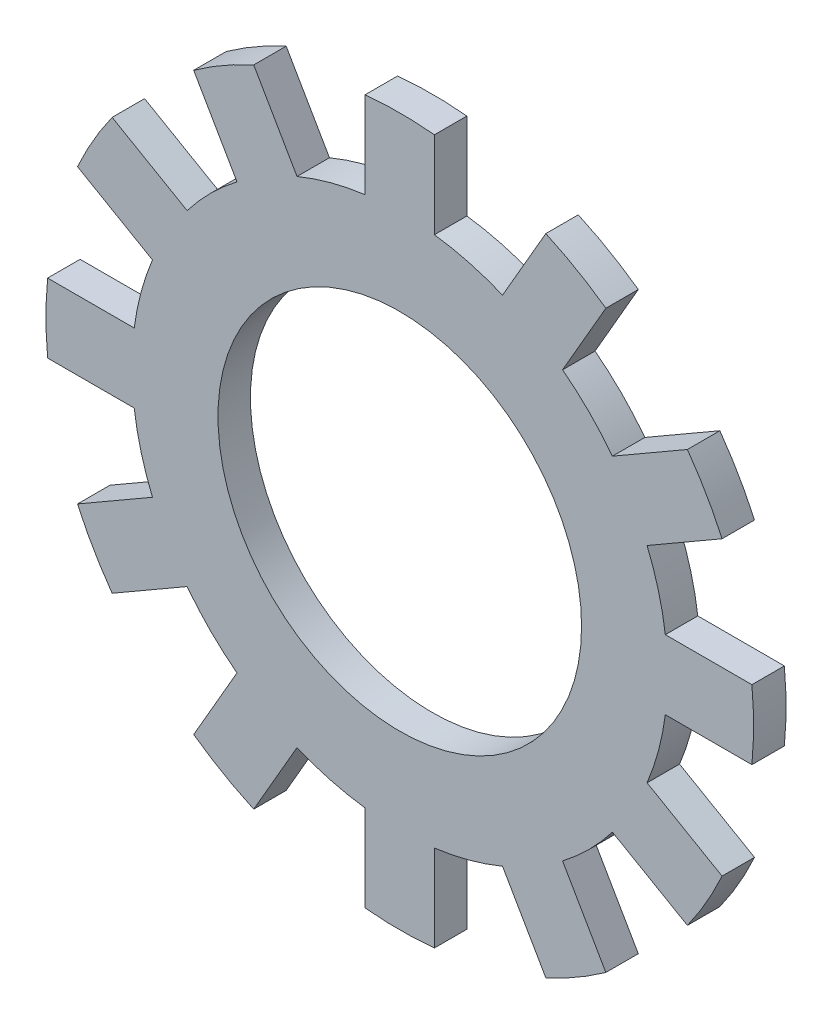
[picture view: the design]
ISO-10303-21;
HEADER;
FILE_DESCRIPTION(('STEP AP214'),'2;1');
FILE_NAME('part.step','',(''),(''),'','','');
FILE_SCHEMA(('AUTOMOTIVE_DESIGN { 1 0 10303 214 1 1 1 1 }'));
ENDSEC;
DATA;
#1=APPLICATION_CONTEXT('core data for automotive mechanical design processes');
#2=APPLICATION_PROTOCOL_DEFINITION('international standard','automotive_design',2000,#1);
#3=PRODUCT_CONTEXT('',#1,'mechanical');
#4=PRODUCT('Part','Part','',(#3));
#5=PRODUCT_RELATED_PRODUCT_CATEGORY('part','',(#4));
#6=PRODUCT_DEFINITION_FORMATION('','',#4);
#7=PRODUCT_DEFINITION_CONTEXT('part definition',#1,'design');
#8=PRODUCT_DEFINITION('design','',#6,#7);
#9=PRODUCT_DEFINITION_SHAPE('','',#8);
#10=(LENGTH_UNIT() NAMED_UNIT(*) SI_UNIT(.MILLI.,.METRE.));
#11=(NAMED_UNIT(*) PLANE_ANGLE_UNIT() SI_UNIT($,.RADIAN.));
#12=(NAMED_UNIT(*) SI_UNIT($,.STERADIAN.) SOLID_ANGLE_UNIT());
#13=UNCERTAINTY_MEASURE_WITH_UNIT(LENGTH_MEASURE(1.E-05),#10,'distance_accuracy_value','');
#14=(GEOMETRIC_REPRESENTATION_CONTEXT(3) GLOBAL_UNCERTAINTY_ASSIGNED_CONTEXT((#13)) GLOBAL_UNIT_ASSIGNED_CONTEXT((#10,
#11,#12)) REPRESENTATION_CONTEXT('',''));
#15=CARTESIAN_POINT('',(0.,0.,0.));
#16=DIRECTION('',(0.,0.,1.));
#17=DIRECTION('',(1.,0.,0.));
#18=AXIS2_PLACEMENT_3D('',#15,#16,#17);
#19=CARTESIAN_POINT('',(0.,0.,0.25));
#20=DIRECTION('',(0.,0.,-1.));
#21=DIRECTION('',(-1.,0.,0.));
#22=AXIS2_PLACEMENT_3D('',#19,#20,#21);
#23=CYLINDRICAL_SURFACE('',#22,2.0625);
#24=DIRECTION('',(0.,0.,-1.));
#25=VECTOR('',#24,1.);
#26=CARTESIAN_POINT('',(-1.25372682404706,1.63770427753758,1.41015672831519));
#27=LINE('',#26,#25);
#28=CARTESIAN_POINT('',(-1.25372682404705,1.63770427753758,0.25));
#29=VERTEX_POINT('',#28);
#30=CARTESIAN_POINT('',(-1.25372682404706,1.63770427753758,0.));
#31=VERTEX_POINT('',#30);
#32=EDGE_CURVE('E363',#29,#31,#27,.T.);
#33=ORIENTED_EDGE('',*,*,#32,.T.);
#34=CARTESIAN_POINT('',(0.,0.,0.));
#35=DIRECTION('',(0.,0.,1.));
#36=DIRECTION('',(1.,0.,0.));
#37=AXIS2_PLACEMENT_3D('',#34,#35,#36);
#38=CIRCLE('',#37,2.0625);
#39=CARTESIAN_POINT('',(-1.63770427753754,1.2537268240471,0.));
#40=VERTEX_POINT('',#39);
#41=EDGE_CURVE('E453',#31,#40,#38,.T.);
#42=ORIENTED_EDGE('',*,*,#41,.T.);
#43=DIRECTION('',(0.,0.,-1.));
#44=VECTOR('',#43,1.);
#45=CARTESIAN_POINT('',(-1.63770427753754,1.2537268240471,1.4101567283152));
#46=LINE('',#45,#44);
#47=CARTESIAN_POINT('',(-1.63770427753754,1.2537268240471,0.25));
#48=VERTEX_POINT('',#47);
#49=EDGE_CURVE('E590',#48,#40,#46,.T.);
#50=ORIENTED_EDGE('',*,*,#49,.F.);
#51=CARTESIAN_POINT('',(0.,0.,0.25));
#52=DIRECTION('',(0.,0.,1.));
#53=DIRECTION('',(1.,0.,0.));
#54=AXIS2_PLACEMENT_3D('',#51,#52,#53);
#55=CIRCLE('',#54,2.0625);
#56=EDGE_CURVE('E50',#29,#48,#55,.T.);
#57=ORIENTED_EDGE('',*,*,#56,.F.);
#58=EDGE_LOOP('',(#33,#42,#50,#57));
#59=FACE_BOUND('',#58,.T.);
#60=ADVANCED_FACE('F41',(#59),#23,.T.);
#61=DIRECTION('',(0.,0.,-1.));
#62=VECTOR('',#61,1.);
#63=CARTESIAN_POINT('',(-0.791430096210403,1.90461141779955,1.41015672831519));
#64=LINE('',#63,#62);
#65=CARTESIAN_POINT('',(-0.791430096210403,1.90461141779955,0.25));
#66=VERTEX_POINT('',#65);
#67=CARTESIAN_POINT('',(-0.791430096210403,1.90461141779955,0.));
#68=VERTEX_POINT('',#67);
#69=EDGE_CURVE('E350',#66,#68,#64,.T.);
#70=ORIENTED_EDGE('',*,*,#69,.F.);
#71=CARTESIAN_POINT('',(-0.266907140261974,2.04515692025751,0.25));
#72=VERTEX_POINT('',#71);
#73=EDGE_CURVE('E11',#72,#66,#55,.T.);
#74=ORIENTED_EDGE('',*,*,#73,.F.);
#75=DIRECTION('',(0.,0.,-1.));
#76=VECTOR('',#75,1.);
#77=CARTESIAN_POINT('',(-0.266907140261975,2.04515692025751,1.11437509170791));
#78=LINE('',#77,#76);
#79=CARTESIAN_POINT('',(-0.266907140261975,2.04515692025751,0.));
#80=VERTEX_POINT('',#79);
#81=EDGE_CURVE('E377',#72,#80,#78,.T.);
#82=ORIENTED_EDGE('',*,*,#81,.T.);
#83=EDGE_CURVE('E45',#80,#68,#38,.T.);
#84=ORIENTED_EDGE('',*,*,#83,.T.);
#85=EDGE_LOOP('',(#70,#74,#82,#84));
#86=FACE_BOUND('',#85,.T.);
#87=ADVANCED_FACE('F360',(#86),#23,.T.);
#88=DIRECTION('',(0.,0.,-1.));
#89=VECTOR('',#88,1.);
#90=CARTESIAN_POINT('',(-1.90461141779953,0.791430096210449,1.4101567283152));
#91=LINE('',#90,#89);
#92=CARTESIAN_POINT('',(-1.90461141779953,0.79143009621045,0.25));
#93=VERTEX_POINT('',#92);
#94=CARTESIAN_POINT('',(-1.90461141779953,0.791430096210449,0.));
#95=VERTEX_POINT('',#94);
#96=EDGE_CURVE('E593',#93,#95,#91,.T.);
#97=ORIENTED_EDGE('',*,*,#96,.T.);
#98=CARTESIAN_POINT('',(-2.04515692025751,0.266907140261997,0.));
#99=VERTEX_POINT('',#98);
#100=EDGE_CURVE('E455',#95,#99,#38,.T.);
#101=ORIENTED_EDGE('',*,*,#100,.T.);
#102=DIRECTION('',(0.,0.,-1.));
#103=VECTOR('',#102,1.);
#104=CARTESIAN_POINT('',(-2.04515692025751,0.266907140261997,1.11437509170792));
#105=LINE('',#104,#103);
#106=CARTESIAN_POINT('',(-2.04515692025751,0.266907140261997,0.25));
#107=VERTEX_POINT('',#106);
#108=EDGE_CURVE('E612',#107,#99,#105,.T.);
#109=ORIENTED_EDGE('',*,*,#108,.F.);
#110=EDGE_CURVE('E1281',#93,#107,#55,.T.);
#111=ORIENTED_EDGE('',*,*,#110,.F.);
#112=EDGE_LOOP('',(#97,#101,#109,#111));
#113=FACE_BOUND('',#112,.T.);
#114=ADVANCED_FACE('F423',(#113),#23,.T.);
#115=DIRECTION('',(0.,0.,-1.));
#116=VECTOR('',#115,1.);
#117=CARTESIAN_POINT('',(-2.04515692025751,-0.266907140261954,1.11437509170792));
#118=LINE('',#117,#116);
#119=CARTESIAN_POINT('',(-2.04515692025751,-0.266907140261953,0.25));
#120=VERTEX_POINT('',#119);
#121=CARTESIAN_POINT('',(-2.04515692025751,-0.266907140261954,0.));
#122=VERTEX_POINT('',#121);
#123=EDGE_CURVE('E615',#120,#122,#118,.T.);
#124=ORIENTED_EDGE('',*,*,#123,.T.);
#125=CARTESIAN_POINT('',(-1.90461141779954,-0.791430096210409,0.));
#126=VERTEX_POINT('',#125);
#127=EDGE_CURVE('E458',#122,#126,#38,.T.);
#128=ORIENTED_EDGE('',*,*,#127,.T.);
#129=DIRECTION('',(0.,0.,-1.));
#130=VECTOR('',#129,1.);
#131=CARTESIAN_POINT('',(-1.90461141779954,-0.791430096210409,1.41015672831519));
#132=LINE('',#131,#130);
#133=CARTESIAN_POINT('',(-1.90461141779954,-0.791430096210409,0.25));
#134=VERTEX_POINT('',#133);
#135=EDGE_CURVE('E636',#134,#126,#132,.T.);
#136=ORIENTED_EDGE('',*,*,#135,.F.);
#137=EDGE_CURVE('E1282',#120,#134,#55,.T.);
#138=ORIENTED_EDGE('',*,*,#137,.F.);
#139=EDGE_LOOP('',(#124,#128,#136,#138));
#140=FACE_BOUND('',#139,.T.);
#141=ADVANCED_FACE('F879',(#140),#23,.T.);
#142=DIRECTION('',(0.,0.,-1.));
#143=VECTOR('',#142,1.);
#144=CARTESIAN_POINT('',(-1.63770427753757,-1.25372682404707,1.41015672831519));
#145=LINE('',#144,#143);
#146=CARTESIAN_POINT('',(-1.63770427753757,-1.25372682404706,0.25));
#147=VERTEX_POINT('',#146);
#148=CARTESIAN_POINT('',(-1.63770427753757,-1.25372682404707,0.));
#149=VERTEX_POINT('',#148);
#150=EDGE_CURVE('E639',#147,#149,#145,.T.);
#151=ORIENTED_EDGE('',*,*,#150,.T.);
#152=CARTESIAN_POINT('',(-1.25372682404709,-1.63770427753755,0.));
#153=VERTEX_POINT('',#152);
#154=EDGE_CURVE('E464',#149,#153,#38,.T.);
#155=ORIENTED_EDGE('',*,*,#154,.T.);
#156=DIRECTION('',(0.,0.,-1.));
#157=VECTOR('',#156,1.);
#158=CARTESIAN_POINT('',(-1.25372682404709,-1.63770427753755,1.4101567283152));
#159=LINE('',#158,#157);
#160=CARTESIAN_POINT('',(-1.25372682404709,-1.63770427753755,0.25));
#161=VERTEX_POINT('',#160);
#162=EDGE_CURVE('E660',#161,#153,#159,.T.);
#163=ORIENTED_EDGE('',*,*,#162,.F.);
#164=EDGE_CURVE('E1285',#147,#161,#55,.T.);
#165=ORIENTED_EDGE('',*,*,#164,.F.);
#166=EDGE_LOOP('',(#151,#155,#163,#165));
#167=FACE_BOUND('',#166,.T.);
#168=ADVANCED_FACE('F871',(#167),#23,.T.);
#169=DIRECTION('',(0.,0.,-1.));
#170=VECTOR('',#169,1.);
#171=CARTESIAN_POINT('',(-0.791430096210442,-1.90461141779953,1.4101567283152));
#172=LINE('',#171,#170);
#173=CARTESIAN_POINT('',(-0.791430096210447,-1.90461141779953,0.25));
#174=VERTEX_POINT('',#173);
#175=CARTESIAN_POINT('',(-0.791430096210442,-1.90461141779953,0.));
#176=VERTEX_POINT('',#175);
#177=EDGE_CURVE('E663',#174,#176,#172,.T.);
#178=ORIENTED_EDGE('',*,*,#177,.T.);
#179=CARTESIAN_POINT('',(-0.26690714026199,-2.04515692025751,0.));
#180=VERTEX_POINT('',#179);
#181=EDGE_CURVE('E470',#176,#180,#38,.T.);
#182=ORIENTED_EDGE('',*,*,#181,.T.);
#183=DIRECTION('',(0.,0.,-1.));
#184=VECTOR('',#183,1.);
#185=CARTESIAN_POINT('',(-0.26690714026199,-2.04515692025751,1.11437509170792));
#186=LINE('',#185,#184);
#187=CARTESIAN_POINT('',(-0.26690714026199,-2.04515692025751,0.25));
#188=VERTEX_POINT('',#187);
#189=EDGE_CURVE('E684',#188,#180,#186,.T.);
#190=ORIENTED_EDGE('',*,*,#189,.F.);
#191=EDGE_CURVE('E1288',#174,#188,#55,.T.);
#192=ORIENTED_EDGE('',*,*,#191,.F.);
#193=EDGE_LOOP('',(#178,#182,#190,#192));
#194=FACE_BOUND('',#193,.T.);
#195=ADVANCED_FACE('F864',(#194),#23,.T.);
#196=DIRECTION('',(0.,0.,-1.));
#197=VECTOR('',#196,1.);
#198=CARTESIAN_POINT('',(0.266907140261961,-2.04515692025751,1.11437509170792));
#199=LINE('',#198,#197);
#200=CARTESIAN_POINT('',(0.26690714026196,-2.04515692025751,0.25));
#201=VERTEX_POINT('',#200);
#202=CARTESIAN_POINT('',(0.266907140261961,-2.04515692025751,0.));
#203=VERTEX_POINT('',#202);
#204=EDGE_CURVE('E687',#201,#203,#199,.T.);
#205=ORIENTED_EDGE('',*,*,#204,.T.);
#206=CARTESIAN_POINT('',(0.791430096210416,-1.90461141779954,0.));
#207=VERTEX_POINT('',#206);
#208=EDGE_CURVE('E476',#203,#207,#38,.T.);
#209=ORIENTED_EDGE('',*,*,#208,.T.);
#210=DIRECTION('',(0.,0.,-1.));
#211=VECTOR('',#210,1.);
#212=CARTESIAN_POINT('',(0.791430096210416,-1.90461141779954,1.41015672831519));
#213=LINE('',#212,#211);
#214=CARTESIAN_POINT('',(0.791430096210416,-1.90461141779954,0.25));
#215=VERTEX_POINT('',#214);
#216=EDGE_CURVE('E708',#215,#207,#213,.T.);
#217=ORIENTED_EDGE('',*,*,#216,.F.);
#218=EDGE_CURVE('E784',#201,#215,#55,.T.);
#219=ORIENTED_EDGE('',*,*,#218,.F.);
#220=EDGE_LOOP('',(#205,#209,#217,#219));
#221=FACE_BOUND('',#220,.T.);
#222=ADVANCED_FACE('F856',(#221),#23,.T.);
#223=DIRECTION('',(0.,0.,-1.));
#224=VECTOR('',#223,1.);
#225=CARTESIAN_POINT('',(1.25372682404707,-1.63770427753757,1.41015672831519));
#226=LINE('',#225,#224);
#227=CARTESIAN_POINT('',(1.25372682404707,-1.63770427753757,0.25));
#228=VERTEX_POINT('',#227);
#229=CARTESIAN_POINT('',(1.25372682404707,-1.63770427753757,0.));
#230=VERTEX_POINT('',#229);
#231=EDGE_CURVE('E711',#228,#230,#226,.T.);
#232=ORIENTED_EDGE('',*,*,#231,.T.);
#233=CARTESIAN_POINT('',(1.63770427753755,-1.25372682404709,0.));
#234=VERTEX_POINT('',#233);
#235=EDGE_CURVE('E482',#230,#234,#38,.T.);
#236=ORIENTED_EDGE('',*,*,#235,.T.);
#237=DIRECTION('',(0.,0.,-1.));
#238=VECTOR('',#237,1.);
#239=CARTESIAN_POINT('',(1.63770427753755,-1.25372682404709,1.41015672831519));
#240=LINE('',#239,#238);
#241=CARTESIAN_POINT('',(1.63770427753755,-1.25372682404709,0.25));
#242=VERTEX_POINT('',#241);
#243=EDGE_CURVE('E732',#242,#234,#240,.T.);
#244=ORIENTED_EDGE('',*,*,#243,.F.);
#245=EDGE_CURVE('E782',#228,#242,#55,.T.);
#246=ORIENTED_EDGE('',*,*,#245,.F.);
#247=EDGE_LOOP('',(#232,#236,#244,#246));
#248=FACE_BOUND('',#247,.T.);
#249=ADVANCED_FACE('F849',(#248),#23,.T.);
#250=DIRECTION('',(0.,0.,-1.));
#251=VECTOR('',#250,1.);
#252=CARTESIAN_POINT('',(1.90461141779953,-0.791430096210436,1.41015672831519));
#253=LINE('',#252,#251);
#254=CARTESIAN_POINT('',(1.90461141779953,-0.79143009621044,0.25));
#255=VERTEX_POINT('',#254);
#256=CARTESIAN_POINT('',(1.90461141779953,-0.791430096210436,0.));
#257=VERTEX_POINT('',#256);
#258=EDGE_CURVE('E735',#255,#257,#253,.T.);
#259=ORIENTED_EDGE('',*,*,#258,.T.);
#260=CARTESIAN_POINT('',(2.04515692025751,-0.266907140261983,0.));
#261=VERTEX_POINT('',#260);
#262=EDGE_CURVE('E488',#257,#261,#38,.T.);
#263=ORIENTED_EDGE('',*,*,#262,.T.);
#264=DIRECTION('',(0.,0.,-1.));
#265=VECTOR('',#264,1.);
#266=CARTESIAN_POINT('',(2.04515692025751,-0.266907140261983,1.11437509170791));
#267=LINE('',#266,#265);
#268=CARTESIAN_POINT('',(2.04515692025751,-0.266907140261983,0.25));
#269=VERTEX_POINT('',#268);
#270=EDGE_CURVE('E755',#269,#261,#267,.T.);
#271=ORIENTED_EDGE('',*,*,#270,.F.);
#272=EDGE_CURVE('E780',#255,#269,#55,.T.);
#273=ORIENTED_EDGE('',*,*,#272,.F.);
#274=EDGE_LOOP('',(#259,#263,#271,#273));
#275=FACE_BOUND('',#274,.T.);
#276=ADVANCED_FACE('F841',(#275),#23,.T.);
#277=DIRECTION('',(0.,0.,-1.));
#278=VECTOR('',#277,1.);
#279=CARTESIAN_POINT('',(2.04515692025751,0.266907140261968,1.11437509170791));
#280=LINE('',#279,#278);
#281=CARTESIAN_POINT('',(2.04515692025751,0.266907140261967,0.25));
#282=VERTEX_POINT('',#281);
#283=CARTESIAN_POINT('',(2.04515692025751,0.266907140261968,0.));
#284=VERTEX_POINT('',#283);
#285=EDGE_CURVE('E507',#282,#284,#280,.T.);
#286=ORIENTED_EDGE('',*,*,#285,.T.);
#287=CARTESIAN_POINT('',(1.90461141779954,0.791430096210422,0.));
#288=VERTEX_POINT('',#287);
#289=EDGE_CURVE('E452',#284,#288,#38,.T.);
#290=ORIENTED_EDGE('',*,*,#289,.T.);
#291=DIRECTION('',(0.,0.,-1.));
#292=VECTOR('',#291,1.);
#293=CARTESIAN_POINT('',(1.90461141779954,0.791430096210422,1.41015672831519));
#294=LINE('',#293,#292);
#295=CARTESIAN_POINT('',(1.90461141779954,0.791430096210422,0.25));
#296=VERTEX_POINT('',#295);
#297=EDGE_CURVE('E505',#296,#288,#294,.T.);
#298=ORIENTED_EDGE('',*,*,#297,.F.);
#299=EDGE_CURVE('E783',#282,#296,#55,.T.);
#300=ORIENTED_EDGE('',*,*,#299,.F.);
#301=EDGE_LOOP('',(#286,#290,#298,#300));
#302=FACE_BOUND('',#301,.T.);
#303=ADVANCED_FACE('F432',(#302),#23,.T.);
#304=DIRECTION('',(0.,0.,-1.));
#305=VECTOR('',#304,1.);
#306=CARTESIAN_POINT('',(1.63770427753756,1.25372682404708,1.41015672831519));
#307=LINE('',#306,#305);
#308=CARTESIAN_POINT('',(1.63770427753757,1.25372682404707,0.25));
#309=VERTEX_POINT('',#308);
#310=CARTESIAN_POINT('',(1.63770427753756,1.25372682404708,0.));
#311=VERTEX_POINT('',#310);
#312=EDGE_CURVE('E518',#309,#311,#307,.T.);
#313=ORIENTED_EDGE('',*,*,#312,.T.);
#314=CARTESIAN_POINT('',(1.25372682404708,1.63770427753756,0.));
#315=VERTEX_POINT('',#314);
#316=EDGE_CURVE('E451',#311,#315,#38,.T.);
#317=ORIENTED_EDGE('',*,*,#316,.T.);
#318=DIRECTION('',(0.,0.,-1.));
#319=VECTOR('',#318,1.);
#320=CARTESIAN_POINT('',(1.25372682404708,1.63770427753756,1.41015672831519));
#321=LINE('',#320,#319);
#322=CARTESIAN_POINT('',(1.25372682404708,1.63770427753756,0.25));
#323=VERTEX_POINT('',#322);
#324=EDGE_CURVE('E441',#323,#315,#321,.T.);
#325=ORIENTED_EDGE('',*,*,#324,.F.);
#326=EDGE_CURVE('E454',#309,#323,#55,.T.);
#327=ORIENTED_EDGE('',*,*,#326,.F.);
#328=EDGE_LOOP('',(#313,#317,#325,#327));
#329=FACE_BOUND('',#328,.T.);
#330=ADVANCED_FACE('F426',(#329),#23,.T.);
#331=DIRECTION('',(0.,0.,-1.));
#332=VECTOR('',#331,1.);
#333=CARTESIAN_POINT('',(0.791430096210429,1.90461141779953,1.41015672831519));
#334=LINE('',#333,#332);
#335=CARTESIAN_POINT('',(0.791430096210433,1.90461141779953,0.25));
#336=VERTEX_POINT('',#335);
#337=CARTESIAN_POINT('',(0.791430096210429,1.90461141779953,0.));
#338=VERTEX_POINT('',#337);
#339=EDGE_CURVE('E437',#336,#338,#334,.T.);
#340=ORIENTED_EDGE('',*,*,#339,.T.);
#341=CARTESIAN_POINT('',(0.266907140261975,2.04515692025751,0.));
#342=VERTEX_POINT('',#341);
#343=EDGE_CURVE('E398',#338,#342,#38,.T.);
#344=ORIENTED_EDGE('',*,*,#343,.T.);
#345=DIRECTION('',(0.,0.,-1.));
#346=VECTOR('',#345,1.);
#347=CARTESIAN_POINT('',(0.266907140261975,2.04515692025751,1.11437509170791));
#348=LINE('',#347,#346);
#349=CARTESIAN_POINT('',(0.266907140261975,2.04515692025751,0.25));
#350=VERTEX_POINT('',#349);
#351=EDGE_CURVE('E381',#350,#342,#348,.T.);
#352=ORIENTED_EDGE('',*,*,#351,.F.);
#353=EDGE_CURVE('E51',#336,#350,#55,.T.);
#354=ORIENTED_EDGE('',*,*,#353,.F.);
#355=EDGE_LOOP('',(#340,#344,#352,#354));
#356=FACE_BOUND('',#355,.T.);
#357=ADVANCED_FACE('F43',(#356),#23,.T.);
#358=CARTESIAN_POINT('',(0.,0.,0.25));
#359=DIRECTION('',(0.,0.,1.));
#360=DIRECTION('',(1.,0.,0.));
#361=AXIS2_PLACEMENT_3D('',#358,#359,#360);
#362=PLANE('',#361);
#363=ORIENTED_EDGE('',*,*,#73,.T.);
#364=DIRECTION('',(-0.499999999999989,0.866025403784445,0.));
#365=VECTOR('',#364,1.);
#366=CARTESIAN_POINT('',(-1.12480015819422,2.48202530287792,0.25));
#367=LINE('',#366,#365);
#368=CARTESIAN_POINT('',(-1.12480015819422,2.48202530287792,0.25));
#369=VERTEX_POINT('',#368);
#370=EDGE_CURVE('E346',#66,#369,#367,.T.);
#371=ORIENTED_EDGE('',*,*,#370,.T.);
#372=CARTESIAN_POINT('',(0.,0.,0.25));
#373=DIRECTION('',(0.,0.,1.));
#374=DIRECTION('',(1.,0.,0.));
#375=AXIS2_PLACEMENT_3D('',#372,#373,#374);
#376=CIRCLE('',#375,2.725);
#377=CARTESIAN_POINT('',(-1.58709688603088,2.21511816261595,0.25));
#378=VERTEX_POINT('',#377);
#379=EDGE_CURVE('E354',#369,#378,#376,.T.);
#380=ORIENTED_EDGE('',*,*,#379,.T.);
#381=DIRECTION('',(0.499999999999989,-0.866025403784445,0.));
#382=VECTOR('',#381,1.);
#383=CARTESIAN_POINT('',(-1.58709688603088,2.21511816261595,0.25));
#384=LINE('',#383,#382);
#385=EDGE_CURVE('E58',#378,#29,#384,.T.);
#386=ORIENTED_EDGE('',*,*,#385,.T.);
#387=ORIENTED_EDGE('',*,*,#56,.T.);
#388=DIRECTION('',(-0.866025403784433,0.50000000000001,0.));
#389=VECTOR('',#388,1.);
#390=CARTESIAN_POINT('',(-2.21511816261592,1.58709688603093,0.25));
#391=LINE('',#390,#389);
#392=CARTESIAN_POINT('',(-2.21511816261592,1.58709688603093,0.25));
#393=VERTEX_POINT('',#392);
#394=EDGE_CURVE('E589',#48,#393,#391,.T.);
#395=ORIENTED_EDGE('',*,*,#394,.T.);
#396=CARTESIAN_POINT('',(0.,0.,0.25));
#397=DIRECTION('',(0.,0.,1.));
#398=DIRECTION('',(1.,0.,0.));
#399=AXIS2_PLACEMENT_3D('',#396,#397,#398);
#400=CIRCLE('',#399,2.725);
#401=CARTESIAN_POINT('',(-2.4820253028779,1.12480015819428,0.25));
#402=VERTEX_POINT('',#401);
#403=EDGE_CURVE('E600',#393,#402,#400,.T.);
#404=ORIENTED_EDGE('',*,*,#403,.T.);
#405=DIRECTION('',(0.866025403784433,-0.50000000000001,0.));
#406=VECTOR('',#405,1.);
#407=CARTESIAN_POINT('',(-2.4820253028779,1.12480015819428,0.25));
#408=LINE('',#407,#406);
#409=EDGE_CURVE('E65',#402,#93,#408,.T.);
#410=ORIENTED_EDGE('',*,*,#409,.T.);
#411=ORIENTED_EDGE('',*,*,#110,.T.);
#412=DIRECTION('',(-1.,0.,0.));
#413=VECTOR('',#412,1.);
#414=CARTESIAN_POINT('',(-2.71189704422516,0.266907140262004,0.25));
#415=LINE('',#414,#413);
#416=CARTESIAN_POINT('',(-2.71189704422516,0.266907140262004,0.25));
#417=VERTEX_POINT('',#416);
#418=EDGE_CURVE('E611',#107,#417,#415,.T.);
#419=ORIENTED_EDGE('',*,*,#418,.T.);
#420=CARTESIAN_POINT('',(0.,0.,0.25));
#421=DIRECTION('',(0.,0.,1.));
#422=DIRECTION('',(1.,0.,0.));
#423=AXIS2_PLACEMENT_3D('',#420,#421,#422);
#424=CIRCLE('',#423,2.725);
#425=CARTESIAN_POINT('',(-2.71189704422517,-0.266907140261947,0.25));
#426=VERTEX_POINT('',#425);
#427=EDGE_CURVE('E623',#417,#426,#424,.T.);
#428=ORIENTED_EDGE('',*,*,#427,.T.);
#429=DIRECTION('',(1.,0.,0.));
#430=VECTOR('',#429,1.);
#431=CARTESIAN_POINT('',(-2.71189704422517,-0.266907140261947,0.25));
#432=LINE('',#431,#430);
#433=EDGE_CURVE('E620',#426,#120,#432,.T.);
#434=ORIENTED_EDGE('',*,*,#433,.T.);
#435=ORIENTED_EDGE('',*,*,#137,.T.);
#436=DIRECTION('',(-0.866025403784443,-0.499999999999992,0.));
#437=VECTOR('',#436,1.);
#438=CARTESIAN_POINT('',(-2.48202530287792,-1.12480015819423,0.25));
#439=LINE('',#438,#437);
#440=CARTESIAN_POINT('',(-2.48202530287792,-1.12480015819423,0.25));
#441=VERTEX_POINT('',#440);
#442=EDGE_CURVE('E635',#134,#441,#439,.T.);
#443=ORIENTED_EDGE('',*,*,#442,.T.);
#444=CARTESIAN_POINT('',(0.,0.,0.25));
#445=DIRECTION('',(0.,0.,1.));
#446=DIRECTION('',(1.,0.,0.));
#447=AXIS2_PLACEMENT_3D('',#444,#445,#446);
#448=CIRCLE('',#447,2.725);
#449=CARTESIAN_POINT('',(-2.21511816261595,-1.58709688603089,0.25));
#450=VERTEX_POINT('',#449);
#451=EDGE_CURVE('E647',#441,#450,#448,.T.);
#452=ORIENTED_EDGE('',*,*,#451,.T.);
#453=DIRECTION('',(0.866025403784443,0.499999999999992,0.));
#454=VECTOR('',#453,1.);
#455=CARTESIAN_POINT('',(-2.21511816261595,-1.58709688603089,0.25));
#456=LINE('',#455,#454);
#457=EDGE_CURVE('E644',#450,#147,#456,.T.);
#458=ORIENTED_EDGE('',*,*,#457,.T.);
#459=ORIENTED_EDGE('',*,*,#164,.T.);
#460=DIRECTION('',(-0.500000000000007,-0.866025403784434,0.));
#461=VECTOR('',#460,1.);
#462=CARTESIAN_POINT('',(-1.58709688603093,-2.21511816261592,0.25));
#463=LINE('',#462,#461);
#464=CARTESIAN_POINT('',(-1.58709688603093,-2.21511816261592,0.25));
#465=VERTEX_POINT('',#464);
#466=EDGE_CURVE('E659',#161,#465,#463,.T.);
#467=ORIENTED_EDGE('',*,*,#466,.T.);
#468=CARTESIAN_POINT('',(0.,0.,0.25));
#469=DIRECTION('',(0.,0.,1.));
#470=DIRECTION('',(1.,0.,0.));
#471=AXIS2_PLACEMENT_3D('',#468,#469,#470);
#472=CIRCLE('',#471,2.725);
#473=CARTESIAN_POINT('',(-1.12480015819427,-2.4820253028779,0.25));
#474=VERTEX_POINT('',#473);
#475=EDGE_CURVE('E671',#465,#474,#472,.T.);
#476=ORIENTED_EDGE('',*,*,#475,.T.);
#477=DIRECTION('',(0.500000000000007,0.866025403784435,0.));
#478=VECTOR('',#477,1.);
#479=CARTESIAN_POINT('',(-1.12480015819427,-2.4820253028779,0.25));
#480=LINE('',#479,#478);
#481=EDGE_CURVE('E668',#474,#174,#480,.T.);
#482=ORIENTED_EDGE('',*,*,#481,.T.);
#483=ORIENTED_EDGE('',*,*,#191,.T.);
#484=DIRECTION('',(0.,-1.,0.));
#485=VECTOR('',#484,1.);
#486=CARTESIAN_POINT('',(-0.266907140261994,-2.71189704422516,0.25));
#487=LINE('',#486,#485);
#488=CARTESIAN_POINT('',(-0.266907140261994,-2.71189704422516,0.25));
#489=VERTEX_POINT('',#488);
#490=EDGE_CURVE('E683',#188,#489,#487,.T.);
#491=ORIENTED_EDGE('',*,*,#490,.T.);
#492=CARTESIAN_POINT('',(0.,0.,0.25));
#493=DIRECTION('',(0.,0.,1.));
#494=DIRECTION('',(1.,0.,0.));
#495=AXIS2_PLACEMENT_3D('',#492,#493,#494);
#496=CIRCLE('',#495,2.725);
#497=CARTESIAN_POINT('',(0.266907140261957,-2.71189704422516,0.25));
#498=VERTEX_POINT('',#497);
#499=EDGE_CURVE('E695',#489,#498,#496,.T.);
#500=ORIENTED_EDGE('',*,*,#499,.T.);
#501=DIRECTION('',(0.,1.,0.));
#502=VECTOR('',#501,1.);
#503=CARTESIAN_POINT('',(0.266907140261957,-2.71189704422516,0.25));
#504=LINE('',#503,#502);
#505=EDGE_CURVE('E692',#498,#201,#504,.T.);
#506=ORIENTED_EDGE('',*,*,#505,.T.);
#507=ORIENTED_EDGE('',*,*,#218,.T.);
#508=DIRECTION('',(0.499999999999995,-0.866025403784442,0.));
#509=VECTOR('',#508,1.);
#510=CARTESIAN_POINT('',(1.12480015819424,-2.48202530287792,0.25));
#511=LINE('',#510,#509);
#512=CARTESIAN_POINT('',(1.12480015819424,-2.48202530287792,0.25));
#513=VERTEX_POINT('',#512);
#514=EDGE_CURVE('E707',#215,#513,#511,.T.);
#515=ORIENTED_EDGE('',*,*,#514,.T.);
#516=CARTESIAN_POINT('',(0.,0.,0.25));
#517=DIRECTION('',(0.,0.,1.));
#518=DIRECTION('',(1.,0.,0.));
#519=AXIS2_PLACEMENT_3D('',#516,#517,#518);
#520=CIRCLE('',#519,2.725);
#521=CARTESIAN_POINT('',(1.5870968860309,-2.21511816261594,0.25));
#522=VERTEX_POINT('',#521);
#523=EDGE_CURVE('E719',#513,#522,#520,.T.);
#524=ORIENTED_EDGE('',*,*,#523,.T.);
#525=DIRECTION('',(-0.499999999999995,0.866025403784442,0.));
#526=VECTOR('',#525,1.);
#527=CARTESIAN_POINT('',(1.5870968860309,-2.21511816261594,0.25));
#528=LINE('',#527,#526);
#529=EDGE_CURVE('E716',#522,#228,#528,.T.);
#530=ORIENTED_EDGE('',*,*,#529,.T.);
#531=ORIENTED_EDGE('',*,*,#245,.T.);
#532=DIRECTION('',(0.866025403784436,-0.500000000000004,0.));
#533=VECTOR('',#532,1.);
#534=CARTESIAN_POINT('',(2.21511816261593,-1.58709688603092,0.25));
#535=LINE('',#534,#533);
#536=CARTESIAN_POINT('',(2.21511816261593,-1.58709688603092,0.25));
#537=VERTEX_POINT('',#536);
#538=EDGE_CURVE('E731',#242,#537,#535,.T.);
#539=ORIENTED_EDGE('',*,*,#538,.T.);
#540=CARTESIAN_POINT('',(0.,0.,0.25));
#541=DIRECTION('',(0.,0.,1.));
#542=DIRECTION('',(1.,0.,0.));
#543=AXIS2_PLACEMENT_3D('',#540,#541,#542);
#544=CIRCLE('',#543,2.725);
#545=CARTESIAN_POINT('',(2.48202530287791,-1.12480015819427,0.25));
#546=VERTEX_POINT('',#545);
#547=EDGE_CURVE('E742',#537,#546,#544,.T.);
#548=ORIENTED_EDGE('',*,*,#547,.T.);
#549=DIRECTION('',(-0.866025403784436,0.500000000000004,0.));
#550=VECTOR('',#549,1.);
#551=CARTESIAN_POINT('',(2.48202530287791,-1.12480015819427,0.25));
#552=LINE('',#551,#550);
#553=EDGE_CURVE('E740',#546,#255,#552,.T.);
#554=ORIENTED_EDGE('',*,*,#553,.T.);
#555=ORIENTED_EDGE('',*,*,#272,.T.);
#556=DIRECTION('',(1.,0.,0.));
#557=VECTOR('',#556,1.);
#558=CARTESIAN_POINT('',(2.71189704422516,-0.266907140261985,0.25));
#559=LINE('',#558,#557);
#560=CARTESIAN_POINT('',(2.71189704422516,-0.266907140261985,0.25));
#561=VERTEX_POINT('',#560);
#562=EDGE_CURVE('E754',#269,#561,#559,.T.);
#563=ORIENTED_EDGE('',*,*,#562,.T.);
#564=CARTESIAN_POINT('',(0.,0.,0.25));
#565=DIRECTION('',(0.,0.,1.));
#566=DIRECTION('',(1.,0.,0.));
#567=AXIS2_PLACEMENT_3D('',#564,#565,#566);
#568=CIRCLE('',#567,2.725);
#569=CARTESIAN_POINT('',(2.71189704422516,0.266907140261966,0.25));
#570=VERTEX_POINT('',#569);
#571=EDGE_CURVE('E763',#561,#570,#568,.T.);
#572=ORIENTED_EDGE('',*,*,#571,.T.);
#573=DIRECTION('',(-1.,0.,0.));
#574=VECTOR('',#573,1.);
#575=CARTESIAN_POINT('',(2.71189704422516,0.266907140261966,0.25));
#576=LINE('',#575,#574);
#577=EDGE_CURVE('E544',#570,#282,#576,.T.);
#578=ORIENTED_EDGE('',*,*,#577,.T.);
#579=ORIENTED_EDGE('',*,*,#299,.T.);
#580=DIRECTION('',(0.86602540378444,0.499999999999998,0.));
#581=VECTOR('',#580,1.);
#582=CARTESIAN_POINT('',(2.48202530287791,1.12480015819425,0.25));
#583=LINE('',#582,#581);
#584=CARTESIAN_POINT('',(2.48202530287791,1.12480015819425,0.25));
#585=VERTEX_POINT('',#584);
#586=EDGE_CURVE('E517',#296,#585,#583,.T.);
#587=ORIENTED_EDGE('',*,*,#586,.T.);
#588=CARTESIAN_POINT('',(0.,0.,0.25));
#589=DIRECTION('',(0.,0.,1.));
#590=DIRECTION('',(1.,0.,0.));
#591=AXIS2_PLACEMENT_3D('',#588,#589,#590);
#592=CIRCLE('',#591,2.725);
#593=CARTESIAN_POINT('',(2.21511816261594,1.5870968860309,0.25));
#594=VERTEX_POINT('',#593);
#595=EDGE_CURVE('E524',#585,#594,#592,.T.);
#596=ORIENTED_EDGE('',*,*,#595,.T.);
#597=DIRECTION('',(-0.86602540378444,-0.499999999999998,0.));
#598=VECTOR('',#597,1.);
#599=CARTESIAN_POINT('',(2.21511816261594,1.5870968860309,0.25));
#600=LINE('',#599,#598);
#601=EDGE_CURVE('E535',#594,#309,#600,.T.);
#602=ORIENTED_EDGE('',*,*,#601,.T.);
#603=ORIENTED_EDGE('',*,*,#326,.T.);
#604=DIRECTION('',(0.500000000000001,0.866025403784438,0.));
#605=VECTOR('',#604,1.);
#606=CARTESIAN_POINT('',(1.58709688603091,2.21511816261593,0.25));
#607=LINE('',#606,#605);
#608=CARTESIAN_POINT('',(1.58709688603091,2.21511816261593,0.25));
#609=VERTEX_POINT('',#608);
#610=EDGE_CURVE('E548',#323,#609,#607,.T.);
#611=ORIENTED_EDGE('',*,*,#610,.T.);
#612=CARTESIAN_POINT('',(0.,0.,0.25));
#613=DIRECTION('',(0.,0.,1.));
#614=DIRECTION('',(1.,0.,0.));
#615=AXIS2_PLACEMENT_3D('',#612,#613,#614);
#616=CIRCLE('',#615,2.725);
#617=CARTESIAN_POINT('',(1.12480015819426,2.48202530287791,0.25));
#618=VERTEX_POINT('',#617);
#619=EDGE_CURVE('E554',#609,#618,#616,.T.);
#620=ORIENTED_EDGE('',*,*,#619,.T.);
#621=DIRECTION('',(-0.500000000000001,-0.866025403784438,0.));
#622=VECTOR('',#621,1.);
#623=CARTESIAN_POINT('',(1.12480015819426,2.48202530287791,0.25));
#624=LINE('',#623,#622);
#625=EDGE_CURVE('E394',#618,#336,#624,.T.);
#626=ORIENTED_EDGE('',*,*,#625,.T.);
#627=ORIENTED_EDGE('',*,*,#353,.T.);
#628=DIRECTION('',(0.,1.,0.));
#629=VECTOR('',#628,1.);
#630=CARTESIAN_POINT('',(0.266907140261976,2.71189704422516,0.25));
#631=LINE('',#630,#629);
#632=CARTESIAN_POINT('',(0.266907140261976,2.71189704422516,0.25));
#633=VERTEX_POINT('',#632);
#634=EDGE_CURVE('E563',#350,#633,#631,.T.);
#635=ORIENTED_EDGE('',*,*,#634,.T.);
#636=CARTESIAN_POINT('',(0.,0.,0.25));
#637=DIRECTION('',(0.,0.,1.));
#638=DIRECTION('',(1.,0.,0.));
#639=AXIS2_PLACEMENT_3D('',#636,#637,#638);
#640=CIRCLE('',#639,2.725);
#641=CARTESIAN_POINT('',(-0.266907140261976,2.71189704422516,0.25));
#642=VERTEX_POINT('',#641);
#643=EDGE_CURVE('E372',#633,#642,#640,.T.);
#644=ORIENTED_EDGE('',*,*,#643,.T.);
#645=DIRECTION('',(0.,-1.,0.));
#646=VECTOR('',#645,1.);
#647=CARTESIAN_POINT('',(-0.266907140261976,2.71189704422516,0.25));
#648=LINE('',#647,#646);
#649=EDGE_CURVE('E368',#642,#72,#648,.T.);
#650=ORIENTED_EDGE('',*,*,#649,.T.);
#651=EDGE_LOOP('',(#363,#371,#380,#386,#387,#395,#404,#410,#411,#419,#428,#434,#435,#443,#452,
#458,#459,#467,#476,#482,#483,#491,#500,#506,#507,#515,#524,#530,#531,#539,#548,#554,#555,#563,
#572,#578,#579,#587,#596,#602,#603,#611,#620,#626,#627,#635,#644,#650));
#652=FACE_BOUND('',#651,.T.);
#653=CARTESIAN_POINT('',(0.,0.,0.25));
#654=DIRECTION('',(0.,0.,1.));
#655=DIRECTION('',(1.,0.,0.));
#656=AXIS2_PLACEMENT_3D('',#653,#654,#655);
#657=CIRCLE('',#656,1.4);
#658=CARTESIAN_POINT('',(1.4,0.,0.25));
#659=VERTEX_POINT('',#658);
#660=EDGE_CURVE('E395',#659,#659,#657,.T.);
#661=ORIENTED_EDGE('',*,*,#660,.F.);
#662=EDGE_LOOP('',(#661));
#663=FACE_BOUND('',#662,.T.);
#664=ADVANCED_FACE('F365',(#652,#663),#362,.T.);
#665=CARTESIAN_POINT('',(0.,0.,0.));
#666=DIRECTION('',(0.,0.,1.));
#667=DIRECTION('',(1.,0.,0.));
#668=AXIS2_PLACEMENT_3D('',#665,#666,#667);
#669=PLANE('',#668);
#670=ORIENTED_EDGE('',*,*,#41,.F.);
#671=DIRECTION('',(0.499999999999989,-0.866025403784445,0.));
#672=VECTOR('',#671,1.);
#673=CARTESIAN_POINT('',(-1.58709688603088,2.21511816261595,0.));
#674=LINE('',#673,#672);
#675=CARTESIAN_POINT('',(-1.58709688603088,2.21511816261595,0.));
#676=VERTEX_POINT('',#675);
#677=EDGE_CURVE('E576',#676,#31,#674,.T.);
#678=ORIENTED_EDGE('',*,*,#677,.F.);
#679=CARTESIAN_POINT('',(0.,0.,0.));
#680=DIRECTION('',(0.,0.,1.));
#681=DIRECTION('',(0.866025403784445,0.499999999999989,0.));
#682=AXIS2_PLACEMENT_3D('',#679,#680,#681);
#683=CIRCLE('',#682,2.725);
#684=CARTESIAN_POINT('',(-1.12480015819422,2.48202530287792,0.));
#685=VERTEX_POINT('',#684);
#686=EDGE_CURVE('E573',#685,#676,#683,.T.);
#687=ORIENTED_EDGE('',*,*,#686,.F.);
#688=DIRECTION('',(-0.499999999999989,0.866025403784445,0.));
#689=VECTOR('',#688,1.);
#690=CARTESIAN_POINT('',(-1.12480015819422,2.48202530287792,0.));
#691=LINE('',#690,#689);
#692=EDGE_CURVE('E355',#68,#685,#691,.T.);
#693=ORIENTED_EDGE('',*,*,#692,.F.);
#694=ORIENTED_EDGE('',*,*,#83,.F.);
#695=DIRECTION('',(0.,-1.,0.));
#696=VECTOR('',#695,1.);
#697=CARTESIAN_POINT('',(-0.266907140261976,2.71189704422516,0.));
#698=LINE('',#697,#696);
#699=CARTESIAN_POINT('',(-0.266907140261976,2.71189704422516,0.));
#700=VERTEX_POINT('',#699);
#701=EDGE_CURVE('E380',#700,#80,#698,.T.);
#702=ORIENTED_EDGE('',*,*,#701,.F.);
#703=CARTESIAN_POINT('',(0.,0.,0.));
#704=DIRECTION('',(0.,0.,1.));
#705=DIRECTION('',(1.,0.,0.));
#706=AXIS2_PLACEMENT_3D('',#703,#704,#705);
#707=CIRCLE('',#706,2.725);
#708=CARTESIAN_POINT('',(0.266907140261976,2.71189704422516,0.));
#709=VERTEX_POINT('',#708);
#710=EDGE_CURVE('E393',#709,#700,#707,.T.);
#711=ORIENTED_EDGE('',*,*,#710,.F.);
#712=DIRECTION('',(0.,1.,0.));
#713=VECTOR('',#712,1.);
#714=CARTESIAN_POINT('',(0.266907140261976,2.71189704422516,0.));
#715=LINE('',#714,#713);
#716=EDGE_CURVE('E384',#342,#709,#715,.T.);
#717=ORIENTED_EDGE('',*,*,#716,.F.);
#718=ORIENTED_EDGE('',*,*,#343,.F.);
#719=DIRECTION('',(-0.500000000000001,-0.866025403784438,0.));
#720=VECTOR('',#719,1.);
#721=CARTESIAN_POINT('',(1.12480015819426,2.48202530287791,0.));
#722=LINE('',#721,#720);
#723=CARTESIAN_POINT('',(1.12480015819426,2.48202530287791,0.));
#724=VERTEX_POINT('',#723);
#725=EDGE_CURVE('E442',#724,#338,#722,.T.);
#726=ORIENTED_EDGE('',*,*,#725,.F.);
#727=CARTESIAN_POINT('',(0.,0.,0.));
#728=DIRECTION('',(0.,0.,1.));
#729=DIRECTION('',(0.866025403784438,-0.500000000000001,0.));
#730=AXIS2_PLACEMENT_3D('',#727,#728,#729);
#731=CIRCLE('',#730,2.725);
#732=CARTESIAN_POINT('',(1.58709688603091,2.21511816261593,0.));
#733=VERTEX_POINT('',#732);
#734=EDGE_CURVE('E551',#733,#724,#731,.T.);
#735=ORIENTED_EDGE('',*,*,#734,.F.);
#736=DIRECTION('',(0.500000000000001,0.866025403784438,0.));
#737=VECTOR('',#736,1.);
#738=CARTESIAN_POINT('',(1.58709688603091,2.21511816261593,0.));
#739=LINE('',#738,#737);
#740=EDGE_CURVE('E545',#315,#733,#739,.T.);
#741=ORIENTED_EDGE('',*,*,#740,.F.);
#742=ORIENTED_EDGE('',*,*,#316,.F.);
#743=DIRECTION('',(-0.86602540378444,-0.499999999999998,0.));
#744=VECTOR('',#743,1.);
#745=CARTESIAN_POINT('',(2.21511816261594,1.5870968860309,0.));
#746=LINE('',#745,#744);
#747=CARTESIAN_POINT('',(2.21511816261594,1.5870968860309,0.));
#748=VERTEX_POINT('',#747);
#749=EDGE_CURVE('E530',#748,#311,#746,.T.);
#750=ORIENTED_EDGE('',*,*,#749,.F.);
#751=CARTESIAN_POINT('',(0.,0.,0.));
#752=DIRECTION('',(0.,0.,1.));
#753=DIRECTION('',(0.499999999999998,-0.86602540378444,0.));
#754=AXIS2_PLACEMENT_3D('',#751,#752,#753);
#755=CIRCLE('',#754,2.725);
#756=CARTESIAN_POINT('',(2.48202530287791,1.12480015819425,0.));
#757=VERTEX_POINT('',#756);
#758=EDGE_CURVE('E522',#757,#748,#755,.T.);
#759=ORIENTED_EDGE('',*,*,#758,.F.);
#760=DIRECTION('',(0.86602540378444,0.499999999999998,0.));
#761=VECTOR('',#760,1.);
#762=CARTESIAN_POINT('',(2.48202530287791,1.12480015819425,0.));
#763=LINE('',#762,#761);
#764=EDGE_CURVE('E514',#288,#757,#763,.T.);
#765=ORIENTED_EDGE('',*,*,#764,.F.);
#766=ORIENTED_EDGE('',*,*,#289,.F.);
#767=DIRECTION('',(-1.,0.,0.));
#768=VECTOR('',#767,1.);
#769=CARTESIAN_POINT('',(2.71189704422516,0.266907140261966,0.));
#770=LINE('',#769,#768);
#771=CARTESIAN_POINT('',(2.71189704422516,0.266907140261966,0.));
#772=VERTEX_POINT('',#771);
#773=EDGE_CURVE('E756',#772,#284,#770,.T.);
#774=ORIENTED_EDGE('',*,*,#773,.F.);
#775=CARTESIAN_POINT('',(0.,0.,0.));
#776=DIRECTION('',(0.,0.,1.));
#777=DIRECTION('',(0.,-1.,0.));
#778=AXIS2_PLACEMENT_3D('',#775,#776,#777);
#779=CIRCLE('',#778,2.725);
#780=CARTESIAN_POINT('',(2.71189704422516,-0.266907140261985,0.));
#781=VERTEX_POINT('',#780);
#782=EDGE_CURVE('E759',#781,#772,#779,.T.);
#783=ORIENTED_EDGE('',*,*,#782,.F.);
#784=DIRECTION('',(1.,0.,0.));
#785=VECTOR('',#784,1.);
#786=CARTESIAN_POINT('',(2.71189704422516,-0.266907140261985,0.));
#787=LINE('',#786,#785);
#788=EDGE_CURVE('E751',#261,#781,#787,.T.);
#789=ORIENTED_EDGE('',*,*,#788,.F.);
#790=ORIENTED_EDGE('',*,*,#262,.F.);
#791=DIRECTION('',(-0.866025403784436,0.500000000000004,0.));
#792=VECTOR('',#791,1.);
#793=CARTESIAN_POINT('',(2.48202530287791,-1.12480015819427,0.));
#794=LINE('',#793,#792);
#795=CARTESIAN_POINT('',(2.48202530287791,-1.12480015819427,0.));
#796=VERTEX_POINT('',#795);
#797=EDGE_CURVE('E733',#796,#257,#794,.T.);
#798=ORIENTED_EDGE('',*,*,#797,.F.);
#799=CARTESIAN_POINT('',(0.,0.,0.));
#800=DIRECTION('',(0.,0.,1.));
#801=DIRECTION('',(-0.500000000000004,-0.866025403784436,0.));
#802=AXIS2_PLACEMENT_3D('',#799,#800,#801);
#803=CIRCLE('',#802,2.725);
#804=CARTESIAN_POINT('',(2.21511816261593,-1.58709688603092,0.));
#805=VERTEX_POINT('',#804);
#806=EDGE_CURVE('E737',#805,#796,#803,.T.);
#807=ORIENTED_EDGE('',*,*,#806,.F.);
#808=DIRECTION('',(0.866025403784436,-0.500000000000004,0.));
#809=VECTOR('',#808,1.);
#810=CARTESIAN_POINT('',(2.21511816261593,-1.58709688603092,0.));
#811=LINE('',#810,#809);
#812=EDGE_CURVE('E728',#234,#805,#811,.T.);
#813=ORIENTED_EDGE('',*,*,#812,.F.);
#814=ORIENTED_EDGE('',*,*,#235,.F.);
#815=DIRECTION('',(-0.499999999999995,0.866025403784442,0.));
#816=VECTOR('',#815,1.);
#817=CARTESIAN_POINT('',(1.5870968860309,-2.21511816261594,0.));
#818=LINE('',#817,#816);
#819=CARTESIAN_POINT('',(1.5870968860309,-2.21511816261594,0.));
#820=VERTEX_POINT('',#819);
#821=EDGE_CURVE('E709',#820,#230,#818,.T.);
#822=ORIENTED_EDGE('',*,*,#821,.F.);
#823=CARTESIAN_POINT('',(0.,0.,0.));
#824=DIRECTION('',(0.,0.,1.));
#825=DIRECTION('',(-0.866025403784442,-0.499999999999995,0.));
#826=AXIS2_PLACEMENT_3D('',#823,#824,#825);
#827=CIRCLE('',#826,2.725);
#828=CARTESIAN_POINT('',(1.12480015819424,-2.48202530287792,0.));
#829=VERTEX_POINT('',#828);
#830=EDGE_CURVE('E713',#829,#820,#827,.T.);
#831=ORIENTED_EDGE('',*,*,#830,.F.);
#832=DIRECTION('',(0.499999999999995,-0.866025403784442,0.));
#833=VECTOR('',#832,1.);
#834=CARTESIAN_POINT('',(1.12480015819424,-2.48202530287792,0.));
#835=LINE('',#834,#833);
#836=EDGE_CURVE('E704',#207,#829,#835,.T.);
#837=ORIENTED_EDGE('',*,*,#836,.F.);
#838=ORIENTED_EDGE('',*,*,#208,.F.);
#839=DIRECTION('',(0.,1.,0.));
#840=VECTOR('',#839,1.);
#841=CARTESIAN_POINT('',(0.266907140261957,-2.71189704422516,0.));
#842=LINE('',#841,#840);
#843=CARTESIAN_POINT('',(0.266907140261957,-2.71189704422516,0.));
#844=VERTEX_POINT('',#843);
#845=EDGE_CURVE('E685',#844,#203,#842,.T.);
#846=ORIENTED_EDGE('',*,*,#845,.F.);
#847=CARTESIAN_POINT('',(0.,0.,0.));
#848=DIRECTION('',(0.,0.,1.));
#849=DIRECTION('',(-1.,0.,0.));
#850=AXIS2_PLACEMENT_3D('',#847,#848,#849);
#851=CIRCLE('',#850,2.725);
#852=CARTESIAN_POINT('',(-0.266907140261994,-2.71189704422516,0.));
#853=VERTEX_POINT('',#852);
#854=EDGE_CURVE('E689',#853,#844,#851,.T.);
#855=ORIENTED_EDGE('',*,*,#854,.F.);
#856=DIRECTION('',(0.,-1.,0.));
#857=VECTOR('',#856,1.);
#858=CARTESIAN_POINT('',(-0.266907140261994,-2.71189704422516,0.));
#859=LINE('',#858,#857);
#860=EDGE_CURVE('E680',#180,#853,#859,.T.);
#861=ORIENTED_EDGE('',*,*,#860,.F.);
#862=ORIENTED_EDGE('',*,*,#181,.F.);
#863=DIRECTION('',(0.500000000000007,0.866025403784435,0.));
#864=VECTOR('',#863,1.);
#865=CARTESIAN_POINT('',(-1.12480015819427,-2.4820253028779,0.));
#866=LINE('',#865,#864);
#867=CARTESIAN_POINT('',(-1.12480015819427,-2.4820253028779,0.));
#868=VERTEX_POINT('',#867);
#869=EDGE_CURVE('E661',#868,#176,#866,.T.);
#870=ORIENTED_EDGE('',*,*,#869,.F.);
#871=CARTESIAN_POINT('',(0.,0.,0.));
#872=DIRECTION('',(0.,0.,1.));
#873=DIRECTION('',(-0.866025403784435,0.500000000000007,0.));
#874=AXIS2_PLACEMENT_3D('',#871,#872,#873);
#875=CIRCLE('',#874,2.725);
#876=CARTESIAN_POINT('',(-1.58709688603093,-2.21511816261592,0.));
#877=VERTEX_POINT('',#876);
#878=EDGE_CURVE('E665',#877,#868,#875,.T.);
#879=ORIENTED_EDGE('',*,*,#878,.F.);
#880=DIRECTION('',(-0.500000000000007,-0.866025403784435,0.));
#881=VECTOR('',#880,1.);
#882=CARTESIAN_POINT('',(-1.58709688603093,-2.21511816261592,0.));
#883=LINE('',#882,#881);
#884=EDGE_CURVE('E656',#153,#877,#883,.T.);
#885=ORIENTED_EDGE('',*,*,#884,.F.);
#886=ORIENTED_EDGE('',*,*,#154,.F.);
#887=DIRECTION('',(0.866025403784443,0.499999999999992,0.));
#888=VECTOR('',#887,1.);
#889=CARTESIAN_POINT('',(-2.21511816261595,-1.58709688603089,0.));
#890=LINE('',#889,#888);
#891=CARTESIAN_POINT('',(-2.21511816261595,-1.58709688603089,0.));
#892=VERTEX_POINT('',#891);
#893=EDGE_CURVE('E637',#892,#149,#890,.T.);
#894=ORIENTED_EDGE('',*,*,#893,.F.);
#895=CARTESIAN_POINT('',(0.,0.,0.));
#896=DIRECTION('',(0.,0.,1.));
#897=DIRECTION('',(-0.499999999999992,0.866025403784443,0.));
#898=AXIS2_PLACEMENT_3D('',#895,#896,#897);
#899=CIRCLE('',#898,2.725);
#900=CARTESIAN_POINT('',(-2.48202530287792,-1.12480015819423,0.));
#901=VERTEX_POINT('',#900);
#902=EDGE_CURVE('E641',#901,#892,#899,.T.);
#903=ORIENTED_EDGE('',*,*,#902,.F.);
#904=DIRECTION('',(-0.866025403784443,-0.499999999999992,0.));
#905=VECTOR('',#904,1.);
#906=CARTESIAN_POINT('',(-2.48202530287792,-1.12480015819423,0.));
#907=LINE('',#906,#905);
#908=EDGE_CURVE('E632',#126,#901,#907,.T.);
#909=ORIENTED_EDGE('',*,*,#908,.F.);
#910=ORIENTED_EDGE('',*,*,#127,.F.);
#911=DIRECTION('',(1.,0.,0.));
#912=VECTOR('',#911,1.);
#913=CARTESIAN_POINT('',(-2.71189704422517,-0.266907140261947,0.));
#914=LINE('',#913,#912);
#915=CARTESIAN_POINT('',(-2.71189704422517,-0.266907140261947,0.));
#916=VERTEX_POINT('',#915);
#917=EDGE_CURVE('E613',#916,#122,#914,.T.);
#918=ORIENTED_EDGE('',*,*,#917,.F.);
#919=CARTESIAN_POINT('',(0.,0.,0.));
#920=DIRECTION('',(0.,0.,1.));
#921=DIRECTION('',(0.,1.,0.));
#922=AXIS2_PLACEMENT_3D('',#919,#920,#921);
#923=CIRCLE('',#922,2.725);
#924=CARTESIAN_POINT('',(-2.71189704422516,0.266907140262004,0.));
#925=VERTEX_POINT('',#924);
#926=EDGE_CURVE('E617',#925,#916,#923,.T.);
#927=ORIENTED_EDGE('',*,*,#926,.F.);
#928=DIRECTION('',(-1.,0.,0.));
#929=VECTOR('',#928,1.);
#930=CARTESIAN_POINT('',(-2.71189704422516,0.266907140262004,0.));
#931=LINE('',#930,#929);
#932=EDGE_CURVE('E608',#99,#925,#931,.T.);
#933=ORIENTED_EDGE('',*,*,#932,.F.);
#934=ORIENTED_EDGE('',*,*,#100,.F.);
#935=DIRECTION('',(0.866025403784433,-0.50000000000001,0.));
#936=VECTOR('',#935,1.);
#937=CARTESIAN_POINT('',(-2.4820253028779,1.12480015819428,0.));
#938=LINE('',#937,#936);
#939=CARTESIAN_POINT('',(-2.4820253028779,1.12480015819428,0.));
#940=VERTEX_POINT('',#939);
#941=EDGE_CURVE('E591',#940,#95,#938,.T.);
#942=ORIENTED_EDGE('',*,*,#941,.F.);
#943=CARTESIAN_POINT('',(0.,0.,0.));
#944=DIRECTION('',(0.,0.,1.));
#945=DIRECTION('',(0.50000000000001,0.866025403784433,0.));
#946=AXIS2_PLACEMENT_3D('',#943,#944,#945);
#947=CIRCLE('',#946,2.725);
#948=CARTESIAN_POINT('',(-2.21511816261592,1.58709688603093,0.));
#949=VERTEX_POINT('',#948);
#950=EDGE_CURVE('E595',#949,#940,#947,.T.);
#951=ORIENTED_EDGE('',*,*,#950,.F.);
#952=DIRECTION('',(-0.866025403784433,0.50000000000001,0.));
#953=VECTOR('',#952,1.);
#954=CARTESIAN_POINT('',(-2.21511816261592,1.58709688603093,0.));
#955=LINE('',#954,#953);
#956=EDGE_CURVE('E586',#40,#949,#955,.T.);
#957=ORIENTED_EDGE('',*,*,#956,.F.);
#958=EDGE_LOOP('',(#670,#678,#687,#693,#694,#702,#711,#717,#718,#726,#735,#741,#742,#750,#759,
#765,#766,#774,#783,#789,#790,#798,#807,#813,#814,#822,#831,#837,#838,#846,#855,#861,#862,#870,
#879,#885,#886,#894,#903,#909,#910,#918,#927,#933,#934,#942,#951,#957));
#959=FACE_BOUND('',#958,.T.);
#960=CARTESIAN_POINT('',(0.,0.,0.));
#961=DIRECTION('',(0.,0.,1.));
#962=DIRECTION('',(1.,0.,0.));
#963=AXIS2_PLACEMENT_3D('',#960,#961,#962);
#964=CIRCLE('',#963,1.4);
#965=CARTESIAN_POINT('',(1.4,0.,0.));
#966=VERTEX_POINT('',#965);
#967=EDGE_CURVE('E375',#966,#966,#964,.T.);
#968=ORIENTED_EDGE('',*,*,#967,.T.);
#969=EDGE_LOOP('',(#968));
#970=FACE_BOUND('',#969,.T.);
#971=ADVANCED_FACE('F402',(#959,#970),#669,.F.);
#972=CARTESIAN_POINT('',(0.,0.,0.25));
#973=DIRECTION('',(0.,0.,-1.));
#974=DIRECTION('',(-1.,0.,0.));
#975=AXIS2_PLACEMENT_3D('',#972,#973,#974);
#976=CYLINDRICAL_SURFACE('',#975,1.4);
#977=ORIENTED_EDGE('',*,*,#660,.T.);
#978=EDGE_LOOP('',(#977));
#979=FACE_BOUND('',#978,.T.);
#980=ORIENTED_EDGE('',*,*,#967,.F.);
#981=EDGE_LOOP('',(#980));
#982=FACE_BOUND('',#981,.T.);
#983=ADVANCED_FACE('F404',(#979,#982),#976,.F.);
#984=CARTESIAN_POINT('',(0.,0.,1.11437509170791));
#985=DIRECTION('',(0.,0.,-1.));
#986=DIRECTION('',(-1.,0.,0.));
#987=AXIS2_PLACEMENT_3D('',#984,#985,#986);
#988=CYLINDRICAL_SURFACE('',#987,2.725);
#989=ORIENTED_EDGE('',*,*,#643,.F.);
#990=DIRECTION('',(0.,0.,-1.));
#991=VECTOR('',#990,1.);
#992=CARTESIAN_POINT('',(0.266907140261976,2.71189704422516,1.11437509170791));
#993=LINE('',#992,#991);
#994=EDGE_CURVE('E391',#633,#709,#993,.T.);
#995=ORIENTED_EDGE('',*,*,#994,.T.);
#996=ORIENTED_EDGE('',*,*,#710,.T.);
#997=DIRECTION('',(0.,0.,-1.));
#998=VECTOR('',#997,1.);
#999=CARTESIAN_POINT('',(-0.266907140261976,2.71189704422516,1.11437509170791));
#1000=LINE('',#999,#998);
#1001=EDGE_CURVE('E386',#642,#700,#1000,.T.);
#1002=ORIENTED_EDGE('',*,*,#1001,.F.);
#1003=EDGE_LOOP('',(#989,#995,#996,#1002));
#1004=FACE_BOUND('',#1003,.T.);
#1005=ADVANCED_FACE('F406',(#1004),#988,.T.);
#1006=CARTESIAN_POINT('',(-0.266907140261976,2.71189704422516,1.11437509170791));
#1007=DIRECTION('',(1.,0.,0.));
#1008=DIRECTION('',(0.,1.,0.));
#1009=AXIS2_PLACEMENT_3D('',#1006,#1007,#1008);
#1010=PLANE('',#1009);
#1011=ORIENTED_EDGE('',*,*,#649,.F.);
#1012=ORIENTED_EDGE('',*,*,#1001,.T.);
#1013=ORIENTED_EDGE('',*,*,#701,.T.);
#1014=ORIENTED_EDGE('',*,*,#81,.F.);
#1015=EDGE_LOOP('',(#1011,#1012,#1013,#1014));
#1016=FACE_BOUND('',#1015,.T.);
#1017=ADVANCED_FACE('F378',(#1016),#1010,.F.);
#1018=CARTESIAN_POINT('',(0.266907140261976,2.71189704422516,1.11437509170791));
#1019=DIRECTION('',(-1.,0.,0.));
#1020=DIRECTION('',(0.,-1.,0.));
#1021=AXIS2_PLACEMENT_3D('',#1018,#1019,#1020);
#1022=PLANE('',#1021);
#1023=ORIENTED_EDGE('',*,*,#634,.F.);
#1024=ORIENTED_EDGE('',*,*,#351,.T.);
#1025=ORIENTED_EDGE('',*,*,#716,.T.);
#1026=ORIENTED_EDGE('',*,*,#994,.F.);
#1027=EDGE_LOOP('',(#1023,#1024,#1025,#1026));
#1028=FACE_BOUND('',#1027,.T.);
#1029=ADVANCED_FACE('F569',(#1028),#1022,.F.);
#1030=CARTESIAN_POINT('',(0.,0.,1.41015672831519));
#1031=DIRECTION('',(0.,0.,-1.));
#1032=DIRECTION('',(-1.,0.,0.));
#1033=AXIS2_PLACEMENT_3D('',#1030,#1031,#1032);
#1034=CYLINDRICAL_SURFACE('',#1033,2.725);
#1035=ORIENTED_EDGE('',*,*,#619,.F.);
#1036=DIRECTION('',(0.,0.,-1.));
#1037=VECTOR('',#1036,1.);
#1038=CARTESIAN_POINT('',(1.58709688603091,2.21511816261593,1.41015672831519));
#1039=LINE('',#1038,#1037);
#1040=EDGE_CURVE('E537',#609,#733,#1039,.T.);
#1041=ORIENTED_EDGE('',*,*,#1040,.T.);
#1042=ORIENTED_EDGE('',*,*,#734,.T.);
#1043=DIRECTION('',(0.,0.,-1.));
#1044=VECTOR('',#1043,1.);
#1045=CARTESIAN_POINT('',(1.12480015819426,2.48202530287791,1.41015672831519));
#1046=LINE('',#1045,#1044);
#1047=EDGE_CURVE('E550',#618,#724,#1046,.T.);
#1048=ORIENTED_EDGE('',*,*,#1047,.F.);
#1049=EDGE_LOOP('',(#1035,#1041,#1042,#1048));
#1050=FACE_BOUND('',#1049,.T.);
#1051=ADVANCED_FACE('F796',(#1050),#1034,.T.);
#1052=CARTESIAN_POINT('',(1.12480015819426,2.48202530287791,1.41015672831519));
#1053=DIRECTION('',(0.866025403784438,-0.500000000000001,0.));
#1054=DIRECTION('',(0.500000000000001,0.866025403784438,0.));
#1055=AXIS2_PLACEMENT_3D('',#1052,#1053,#1054);
#1056=PLANE('',#1055);
#1057=ORIENTED_EDGE('',*,*,#625,.F.);
#1058=ORIENTED_EDGE('',*,*,#1047,.T.);
#1059=ORIENTED_EDGE('',*,*,#725,.T.);
#1060=ORIENTED_EDGE('',*,*,#339,.F.);
#1061=EDGE_LOOP('',(#1057,#1058,#1059,#1060));
#1062=FACE_BOUND('',#1061,.T.);
#1063=ADVANCED_FACE('F797',(#1062),#1056,.F.);
#1064=CARTESIAN_POINT('',(1.58709688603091,2.21511816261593,1.41015672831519));
#1065=DIRECTION('',(-0.866025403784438,0.500000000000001,0.));
#1066=DIRECTION('',(-0.500000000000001,-0.866025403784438,0.));
#1067=AXIS2_PLACEMENT_3D('',#1064,#1065,#1066);
#1068=PLANE('',#1067);
#1069=ORIENTED_EDGE('',*,*,#610,.F.);
#1070=ORIENTED_EDGE('',*,*,#324,.T.);
#1071=ORIENTED_EDGE('',*,*,#740,.T.);
#1072=ORIENTED_EDGE('',*,*,#1040,.F.);
#1073=EDGE_LOOP('',(#1069,#1070,#1071,#1072));
#1074=FACE_BOUND('',#1073,.T.);
#1075=ADVANCED_FACE('F790',(#1074),#1068,.F.);
#1076=CARTESIAN_POINT('',(0.,0.,1.41015672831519));
#1077=DIRECTION('',(0.,0.,-1.));
#1078=DIRECTION('',(-1.,0.,0.));
#1079=AXIS2_PLACEMENT_3D('',#1076,#1077,#1078);
#1080=CYLINDRICAL_SURFACE('',#1079,2.725);
#1081=ORIENTED_EDGE('',*,*,#595,.F.);
#1082=DIRECTION('',(0.,0.,-1.));
#1083=VECTOR('',#1082,1.);
#1084=CARTESIAN_POINT('',(2.48202530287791,1.12480015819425,1.41015672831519));
#1085=LINE('',#1084,#1083);
#1086=EDGE_CURVE('E534',#585,#757,#1085,.T.);
#1087=ORIENTED_EDGE('',*,*,#1086,.T.);
#1088=ORIENTED_EDGE('',*,*,#758,.T.);
#1089=DIRECTION('',(0.,0.,-1.));
#1090=VECTOR('',#1089,1.);
#1091=CARTESIAN_POINT('',(2.21511816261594,1.5870968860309,1.41015672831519));
#1092=LINE('',#1091,#1090);
#1093=EDGE_CURVE('E532',#594,#748,#1092,.T.);
#1094=ORIENTED_EDGE('',*,*,#1093,.F.);
#1095=EDGE_LOOP('',(#1081,#1087,#1088,#1094));
#1096=FACE_BOUND('',#1095,.T.);
#1097=ADVANCED_FACE('F805',(#1096),#1080,.T.);
#1098=CARTESIAN_POINT('',(2.21511816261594,1.5870968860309,1.41015672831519));
#1099=DIRECTION('',(0.499999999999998,-0.86602540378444,0.));
#1100=DIRECTION('',(0.86602540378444,0.499999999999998,0.));
#1101=AXIS2_PLACEMENT_3D('',#1098,#1099,#1100);
#1102=PLANE('',#1101);
#1103=ORIENTED_EDGE('',*,*,#601,.F.);
#1104=ORIENTED_EDGE('',*,*,#1093,.T.);
#1105=ORIENTED_EDGE('',*,*,#749,.T.);
#1106=ORIENTED_EDGE('',*,*,#312,.F.);
#1107=EDGE_LOOP('',(#1103,#1104,#1105,#1106));
#1108=FACE_BOUND('',#1107,.T.);
#1109=ADVANCED_FACE('F946',(#1108),#1102,.F.);
#1110=CARTESIAN_POINT('',(2.48202530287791,1.12480015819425,1.41015672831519));
#1111=DIRECTION('',(-0.499999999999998,0.86602540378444,0.));
#1112=DIRECTION('',(-0.86602540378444,-0.499999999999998,0.));
#1113=AXIS2_PLACEMENT_3D('',#1110,#1111,#1112);
#1114=PLANE('',#1113);
#1115=ORIENTED_EDGE('',*,*,#586,.F.);
#1116=ORIENTED_EDGE('',*,*,#297,.T.);
#1117=ORIENTED_EDGE('',*,*,#764,.T.);
#1118=ORIENTED_EDGE('',*,*,#1086,.F.);
#1119=EDGE_LOOP('',(#1115,#1116,#1117,#1118));
#1120=FACE_BOUND('',#1119,.T.);
#1121=ADVANCED_FACE('F513',(#1120),#1114,.F.);
#1122=CARTESIAN_POINT('',(0.,0.,1.11437509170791));
#1123=DIRECTION('',(0.,0.,-1.));
#1124=DIRECTION('',(-1.,0.,0.));
#1125=AXIS2_PLACEMENT_3D('',#1122,#1123,#1124);
#1126=CYLINDRICAL_SURFACE('',#1125,2.725);
#1127=ORIENTED_EDGE('',*,*,#571,.F.);
#1128=DIRECTION('',(0.,0.,-1.));
#1129=VECTOR('',#1128,1.);
#1130=CARTESIAN_POINT('',(2.71189704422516,-0.266907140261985,1.11437509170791));
#1131=LINE('',#1130,#1129);
#1132=EDGE_CURVE('E528',#561,#781,#1131,.T.);
#1133=ORIENTED_EDGE('',*,*,#1132,.T.);
#1134=ORIENTED_EDGE('',*,*,#782,.T.);
#1135=DIRECTION('',(0.,0.,-1.));
#1136=VECTOR('',#1135,1.);
#1137=CARTESIAN_POINT('',(2.71189704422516,0.266907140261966,1.11437509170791));
#1138=LINE('',#1137,#1136);
#1139=EDGE_CURVE('E758',#570,#772,#1138,.T.);
#1140=ORIENTED_EDGE('',*,*,#1139,.F.);
#1141=EDGE_LOOP('',(#1127,#1133,#1134,#1140));
#1142=FACE_BOUND('',#1141,.T.);
#1143=ADVANCED_FACE('F779',(#1142),#1126,.T.);
#1144=CARTESIAN_POINT('',(2.71189704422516,0.266907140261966,1.11437509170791));
#1145=DIRECTION('',(0.,-1.,0.));
#1146=DIRECTION('',(1.,0.,0.));
#1147=AXIS2_PLACEMENT_3D('',#1144,#1145,#1146);
#1148=PLANE('',#1147);
#1149=ORIENTED_EDGE('',*,*,#577,.F.);
#1150=ORIENTED_EDGE('',*,*,#1139,.T.);
#1151=ORIENTED_EDGE('',*,*,#773,.T.);
#1152=ORIENTED_EDGE('',*,*,#285,.F.);
#1153=EDGE_LOOP('',(#1149,#1150,#1151,#1152));
#1154=FACE_BOUND('',#1153,.T.);
#1155=ADVANCED_FACE('F974',(#1154),#1148,.F.);
#1156=CARTESIAN_POINT('',(2.71189704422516,-0.266907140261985,1.11437509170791));
#1157=DIRECTION('',(0.,1.,0.));
#1158=DIRECTION('',(-1.,0.,0.));
#1159=AXIS2_PLACEMENT_3D('',#1156,#1157,#1158);
#1160=PLANE('',#1159);
#1161=ORIENTED_EDGE('',*,*,#562,.F.);
#1162=ORIENTED_EDGE('',*,*,#270,.T.);
#1163=ORIENTED_EDGE('',*,*,#788,.T.);
#1164=ORIENTED_EDGE('',*,*,#1132,.F.);
#1165=EDGE_LOOP('',(#1161,#1162,#1163,#1164));
#1166=FACE_BOUND('',#1165,.T.);
#1167=ADVANCED_FACE('F772',(#1166),#1160,.F.);
#1168=CARTESIAN_POINT('',(0.,0.,1.41015672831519));
#1169=DIRECTION('',(0.,0.,-1.));
#1170=DIRECTION('',(-1.,0.,0.));
#1171=AXIS2_PLACEMENT_3D('',#1168,#1169,#1170);
#1172=CYLINDRICAL_SURFACE('',#1171,2.725);
#1173=ORIENTED_EDGE('',*,*,#547,.F.);
#1174=DIRECTION('',(0.,0.,-1.));
#1175=VECTOR('',#1174,1.);
#1176=CARTESIAN_POINT('',(2.21511816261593,-1.58709688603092,1.41015672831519));
#1177=LINE('',#1176,#1175);
#1178=EDGE_CURVE('E718',#537,#805,#1177,.T.);
#1179=ORIENTED_EDGE('',*,*,#1178,.T.);
#1180=ORIENTED_EDGE('',*,*,#806,.T.);
#1181=DIRECTION('',(0.,0.,-1.));
#1182=VECTOR('',#1181,1.);
#1183=CARTESIAN_POINT('',(2.48202530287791,-1.12480015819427,1.41015672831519));
#1184=LINE('',#1183,#1182);
#1185=EDGE_CURVE('E736',#546,#796,#1184,.T.);
#1186=ORIENTED_EDGE('',*,*,#1185,.F.);
#1187=EDGE_LOOP('',(#1173,#1179,#1180,#1186));
#1188=FACE_BOUND('',#1187,.T.);
#1189=ADVANCED_FACE('F994',(#1188),#1172,.T.);
#1190=CARTESIAN_POINT('',(2.48202530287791,-1.12480015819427,1.41015672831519));
#1191=DIRECTION('',(-0.500000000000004,-0.866025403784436,0.));
#1192=DIRECTION('',(0.866025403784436,-0.500000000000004,0.));
#1193=AXIS2_PLACEMENT_3D('',#1190,#1191,#1192);
#1194=PLANE('',#1193);
#1195=ORIENTED_EDGE('',*,*,#553,.F.);
#1196=ORIENTED_EDGE('',*,*,#1185,.T.);
#1197=ORIENTED_EDGE('',*,*,#797,.T.);
#1198=ORIENTED_EDGE('',*,*,#258,.F.);
#1199=EDGE_LOOP('',(#1195,#1196,#1197,#1198));
#1200=FACE_BOUND('',#1199,.T.);
#1201=ADVANCED_FACE('F1004',(#1200),#1194,.F.);
#1202=CARTESIAN_POINT('',(2.21511816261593,-1.58709688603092,1.41015672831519));
#1203=DIRECTION('',(0.500000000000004,0.866025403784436,0.));
#1204=DIRECTION('',(-0.866025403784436,0.500000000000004,0.));
#1205=AXIS2_PLACEMENT_3D('',#1202,#1203,#1204);
#1206=PLANE('',#1205);
#1207=ORIENTED_EDGE('',*,*,#538,.F.);
#1208=ORIENTED_EDGE('',*,*,#243,.T.);
#1209=ORIENTED_EDGE('',*,*,#812,.T.);
#1210=ORIENTED_EDGE('',*,*,#1178,.F.);
#1211=EDGE_LOOP('',(#1207,#1208,#1209,#1210));
#1212=FACE_BOUND('',#1211,.T.);
#1213=ADVANCED_FACE('F1015',(#1212),#1206,.F.);
#1214=CARTESIAN_POINT('',(0.,0.,1.41015672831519));
#1215=DIRECTION('',(0.,0.,-1.));
#1216=DIRECTION('',(-1.,0.,0.));
#1217=AXIS2_PLACEMENT_3D('',#1214,#1215,#1216);
#1218=CYLINDRICAL_SURFACE('',#1217,2.725);
#1219=ORIENTED_EDGE('',*,*,#523,.F.);
#1220=DIRECTION('',(0.,0.,-1.));
#1221=VECTOR('',#1220,1.);
#1222=CARTESIAN_POINT('',(1.12480015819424,-2.48202530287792,1.41015672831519));
#1223=LINE('',#1222,#1221);
#1224=EDGE_CURVE('E694',#513,#829,#1223,.T.);
#1225=ORIENTED_EDGE('',*,*,#1224,.T.);
#1226=ORIENTED_EDGE('',*,*,#830,.T.);
#1227=DIRECTION('',(0.,0.,-1.));
#1228=VECTOR('',#1227,1.);
#1229=CARTESIAN_POINT('',(1.5870968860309,-2.21511816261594,1.41015672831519));
#1230=LINE('',#1229,#1228);
#1231=EDGE_CURVE('E712',#522,#820,#1230,.T.);
#1232=ORIENTED_EDGE('',*,*,#1231,.F.);
#1233=EDGE_LOOP('',(#1219,#1225,#1226,#1232));
#1234=FACE_BOUND('',#1233,.T.);
#1235=ADVANCED_FACE('F1026',(#1234),#1218,.T.);
#1236=CARTESIAN_POINT('',(1.5870968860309,-2.21511816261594,1.41015672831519));
#1237=DIRECTION('',(-0.866025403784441,-0.499999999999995,0.));
#1238=DIRECTION('',(0.499999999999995,-0.866025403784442,0.));
#1239=AXIS2_PLACEMENT_3D('',#1236,#1237,#1238);
#1240=PLANE('',#1239);
#1241=ORIENTED_EDGE('',*,*,#529,.F.);
#1242=ORIENTED_EDGE('',*,*,#1231,.T.);
#1243=ORIENTED_EDGE('',*,*,#821,.T.);
#1244=ORIENTED_EDGE('',*,*,#231,.F.);
#1245=EDGE_LOOP('',(#1241,#1242,#1243,#1244));
#1246=FACE_BOUND('',#1245,.T.);
#1247=ADVANCED_FACE('F1037',(#1246),#1240,.F.);
#1248=CARTESIAN_POINT('',(1.12480015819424,-2.48202530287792,1.41015672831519));
#1249=DIRECTION('',(0.866025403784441,0.499999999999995,0.));
#1250=DIRECTION('',(-0.499999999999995,0.866025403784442,0.));
#1251=AXIS2_PLACEMENT_3D('',#1248,#1249,#1250);
#1252=PLANE('',#1251);
#1253=ORIENTED_EDGE('',*,*,#514,.F.);
#1254=ORIENTED_EDGE('',*,*,#216,.T.);
#1255=ORIENTED_EDGE('',*,*,#836,.T.);
#1256=ORIENTED_EDGE('',*,*,#1224,.F.);
#1257=EDGE_LOOP('',(#1253,#1254,#1255,#1256));
#1258=FACE_BOUND('',#1257,.T.);
#1259=ADVANCED_FACE('F1048',(#1258),#1252,.F.);
#1260=CARTESIAN_POINT('',(0.,0.,1.11437509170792));
#1261=DIRECTION('',(0.,0.,-1.));
#1262=DIRECTION('',(-1.,0.,0.));
#1263=AXIS2_PLACEMENT_3D('',#1260,#1261,#1262);
#1264=CYLINDRICAL_SURFACE('',#1263,2.725);
#1265=ORIENTED_EDGE('',*,*,#499,.F.);
#1266=DIRECTION('',(0.,0.,-1.));
#1267=VECTOR('',#1266,1.);
#1268=CARTESIAN_POINT('',(-0.266907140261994,-2.71189704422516,1.11437509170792));
#1269=LINE('',#1268,#1267);
#1270=EDGE_CURVE('E670',#489,#853,#1269,.T.);
#1271=ORIENTED_EDGE('',*,*,#1270,.T.);
#1272=ORIENTED_EDGE('',*,*,#854,.T.);
#1273=DIRECTION('',(0.,0.,-1.));
#1274=VECTOR('',#1273,1.);
#1275=CARTESIAN_POINT('',(0.266907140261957,-2.71189704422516,1.11437509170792));
#1276=LINE('',#1275,#1274);
#1277=EDGE_CURVE('E688',#498,#844,#1276,.T.);
#1278=ORIENTED_EDGE('',*,*,#1277,.F.);
#1279=EDGE_LOOP('',(#1265,#1271,#1272,#1278));
#1280=FACE_BOUND('',#1279,.T.);
#1281=ADVANCED_FACE('F1059',(#1280),#1264,.T.);
#1282=CARTESIAN_POINT('',(0.266907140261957,-2.71189704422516,1.11437509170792));
#1283=DIRECTION('',(-1.,0.,0.));
#1284=DIRECTION('',(0.,-1.,0.));
#1285=AXIS2_PLACEMENT_3D('',#1282,#1283,#1284);
#1286=PLANE('',#1285);
#1287=ORIENTED_EDGE('',*,*,#505,.F.);
#1288=ORIENTED_EDGE('',*,*,#1277,.T.);
#1289=ORIENTED_EDGE('',*,*,#845,.T.);
#1290=ORIENTED_EDGE('',*,*,#204,.F.);
#1291=EDGE_LOOP('',(#1287,#1288,#1289,#1290));
#1292=FACE_BOUND('',#1291,.T.);
#1293=ADVANCED_FACE('F1070',(#1292),#1286,.F.);
#1294=CARTESIAN_POINT('',(-0.266907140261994,-2.71189704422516,1.11437509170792));
#1295=DIRECTION('',(1.,0.,0.));
#1296=DIRECTION('',(0.,1.,0.));
#1297=AXIS2_PLACEMENT_3D('',#1294,#1295,#1296);
#1298=PLANE('',#1297);
#1299=ORIENTED_EDGE('',*,*,#490,.F.);
#1300=ORIENTED_EDGE('',*,*,#189,.T.);
#1301=ORIENTED_EDGE('',*,*,#860,.T.);
#1302=ORIENTED_EDGE('',*,*,#1270,.F.);
#1303=EDGE_LOOP('',(#1299,#1300,#1301,#1302));
#1304=FACE_BOUND('',#1303,.T.);
#1305=ADVANCED_FACE('F1081',(#1304),#1298,.F.);
#1306=CARTESIAN_POINT('',(0.,0.,1.4101567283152));
#1307=DIRECTION('',(0.,0.,-1.));
#1308=DIRECTION('',(-1.,0.,0.));
#1309=AXIS2_PLACEMENT_3D('',#1306,#1307,#1308);
#1310=CYLINDRICAL_SURFACE('',#1309,2.725);
#1311=ORIENTED_EDGE('',*,*,#475,.F.);
#1312=DIRECTION('',(0.,0.,-1.));
#1313=VECTOR('',#1312,1.);
#1314=CARTESIAN_POINT('',(-1.58709688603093,-2.21511816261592,1.4101567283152));
#1315=LINE('',#1314,#1313);
#1316=EDGE_CURVE('E646',#465,#877,#1315,.T.);
#1317=ORIENTED_EDGE('',*,*,#1316,.T.);
#1318=ORIENTED_EDGE('',*,*,#878,.T.);
#1319=DIRECTION('',(0.,0.,-1.));
#1320=VECTOR('',#1319,1.);
#1321=CARTESIAN_POINT('',(-1.12480015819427,-2.4820253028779,1.4101567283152));
#1322=LINE('',#1321,#1320);
#1323=EDGE_CURVE('E664',#474,#868,#1322,.T.);
#1324=ORIENTED_EDGE('',*,*,#1323,.F.);
#1325=EDGE_LOOP('',(#1311,#1317,#1318,#1324));
#1326=FACE_BOUND('',#1325,.T.);
#1327=ADVANCED_FACE('F1092',(#1326),#1310,.T.);
#1328=CARTESIAN_POINT('',(-1.12480015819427,-2.4820253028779,1.4101567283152));
#1329=DIRECTION('',(-0.866025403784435,0.500000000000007,0.));
#1330=DIRECTION('',(-0.500000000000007,-0.866025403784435,0.));
#1331=AXIS2_PLACEMENT_3D('',#1328,#1329,#1330);
#1332=PLANE('',#1331);
#1333=ORIENTED_EDGE('',*,*,#481,.F.);
#1334=ORIENTED_EDGE('',*,*,#1323,.T.);
#1335=ORIENTED_EDGE('',*,*,#869,.T.);
#1336=ORIENTED_EDGE('',*,*,#177,.F.);
#1337=EDGE_LOOP('',(#1333,#1334,#1335,#1336));
#1338=FACE_BOUND('',#1337,.T.);
#1339=ADVANCED_FACE('F1103',(#1338),#1332,.F.);
#1340=CARTESIAN_POINT('',(-1.58709688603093,-2.21511816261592,1.4101567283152));
#1341=DIRECTION('',(0.866025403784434,-0.500000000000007,0.));
#1342=DIRECTION('',(0.500000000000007,0.866025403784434,0.));
#1343=AXIS2_PLACEMENT_3D('',#1340,#1341,#1342);
#1344=PLANE('',#1343);
#1345=ORIENTED_EDGE('',*,*,#466,.F.);
#1346=ORIENTED_EDGE('',*,*,#162,.T.);
#1347=ORIENTED_EDGE('',*,*,#884,.T.);
#1348=ORIENTED_EDGE('',*,*,#1316,.F.);
#1349=EDGE_LOOP('',(#1345,#1346,#1347,#1348));
#1350=FACE_BOUND('',#1349,.T.);
#1351=ADVANCED_FACE('F1114',(#1350),#1344,.F.);
#1352=CARTESIAN_POINT('',(0.,0.,1.41015672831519));
#1353=DIRECTION('',(0.,0.,-1.));
#1354=DIRECTION('',(-1.,0.,0.));
#1355=AXIS2_PLACEMENT_3D('',#1352,#1353,#1354);
#1356=CYLINDRICAL_SURFACE('',#1355,2.725);
#1357=ORIENTED_EDGE('',*,*,#451,.F.);
#1358=DIRECTION('',(0.,0.,-1.));
#1359=VECTOR('',#1358,1.);
#1360=CARTESIAN_POINT('',(-2.48202530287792,-1.12480015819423,1.41015672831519));
#1361=LINE('',#1360,#1359);
#1362=EDGE_CURVE('E622',#441,#901,#1361,.T.);
#1363=ORIENTED_EDGE('',*,*,#1362,.T.);
#1364=ORIENTED_EDGE('',*,*,#902,.T.);
#1365=DIRECTION('',(0.,0.,-1.));
#1366=VECTOR('',#1365,1.);
#1367=CARTESIAN_POINT('',(-2.21511816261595,-1.58709688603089,1.41015672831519));
#1368=LINE('',#1367,#1366);
#1369=EDGE_CURVE('E640',#450,#892,#1368,.T.);
#1370=ORIENTED_EDGE('',*,*,#1369,.F.);
#1371=EDGE_LOOP('',(#1357,#1363,#1364,#1370));
#1372=FACE_BOUND('',#1371,.T.);
#1373=ADVANCED_FACE('F1125',(#1372),#1356,.T.);
#1374=CARTESIAN_POINT('',(-2.21511816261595,-1.58709688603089,1.41015672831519));
#1375=DIRECTION('',(-0.499999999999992,0.866025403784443,0.));
#1376=DIRECTION('',(-0.866025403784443,-0.499999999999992,0.));
#1377=AXIS2_PLACEMENT_3D('',#1374,#1375,#1376);
#1378=PLANE('',#1377);
#1379=ORIENTED_EDGE('',*,*,#457,.F.);
#1380=ORIENTED_EDGE('',*,*,#1369,.T.);
#1381=ORIENTED_EDGE('',*,*,#893,.T.);
#1382=ORIENTED_EDGE('',*,*,#150,.F.);
#1383=EDGE_LOOP('',(#1379,#1380,#1381,#1382));
#1384=FACE_BOUND('',#1383,.T.);
#1385=ADVANCED_FACE('F1136',(#1384),#1378,.F.);
#1386=CARTESIAN_POINT('',(-2.48202530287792,-1.12480015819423,1.41015672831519));
#1387=DIRECTION('',(0.499999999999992,-0.866025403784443,0.));
#1388=DIRECTION('',(0.866025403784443,0.499999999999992,0.));
#1389=AXIS2_PLACEMENT_3D('',#1386,#1387,#1388);
#1390=PLANE('',#1389);
#1391=ORIENTED_EDGE('',*,*,#442,.F.);
#1392=ORIENTED_EDGE('',*,*,#135,.T.);
#1393=ORIENTED_EDGE('',*,*,#908,.T.);
#1394=ORIENTED_EDGE('',*,*,#1362,.F.);
#1395=EDGE_LOOP('',(#1391,#1392,#1393,#1394));
#1396=FACE_BOUND('',#1395,.T.);
#1397=ADVANCED_FACE('F1147',(#1396),#1390,.F.);
#1398=CARTESIAN_POINT('',(0.,0.,1.11437509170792));
#1399=DIRECTION('',(0.,0.,-1.));
#1400=DIRECTION('',(-1.,0.,0.));
#1401=AXIS2_PLACEMENT_3D('',#1398,#1399,#1400);
#1402=CYLINDRICAL_SURFACE('',#1401,2.725);
#1403=ORIENTED_EDGE('',*,*,#427,.F.);
#1404=DIRECTION('',(0.,0.,-1.));
#1405=VECTOR('',#1404,1.);
#1406=CARTESIAN_POINT('',(-2.71189704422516,0.266907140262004,1.11437509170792));
#1407=LINE('',#1406,#1405);
#1408=EDGE_CURVE('E599',#417,#925,#1407,.T.);
#1409=ORIENTED_EDGE('',*,*,#1408,.T.);
#1410=ORIENTED_EDGE('',*,*,#926,.T.);
#1411=DIRECTION('',(0.,0.,-1.));
#1412=VECTOR('',#1411,1.);
#1413=CARTESIAN_POINT('',(-2.71189704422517,-0.266907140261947,1.11437509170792));
#1414=LINE('',#1413,#1412);
#1415=EDGE_CURVE('E616',#426,#916,#1414,.T.);
#1416=ORIENTED_EDGE('',*,*,#1415,.F.);
#1417=EDGE_LOOP('',(#1403,#1409,#1410,#1416));
#1418=FACE_BOUND('',#1417,.T.);
#1419=ADVANCED_FACE('F1158',(#1418),#1402,.T.);
#1420=CARTESIAN_POINT('',(-2.71189704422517,-0.266907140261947,1.11437509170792));
#1421=DIRECTION('',(0.,1.,0.));
#1422=DIRECTION('',(-1.,0.,0.));
#1423=AXIS2_PLACEMENT_3D('',#1420,#1421,#1422);
#1424=PLANE('',#1423);
#1425=ORIENTED_EDGE('',*,*,#433,.F.);
#1426=ORIENTED_EDGE('',*,*,#1415,.T.);
#1427=ORIENTED_EDGE('',*,*,#917,.T.);
#1428=ORIENTED_EDGE('',*,*,#123,.F.);
#1429=EDGE_LOOP('',(#1425,#1426,#1427,#1428));
#1430=FACE_BOUND('',#1429,.T.);
#1431=ADVANCED_FACE('F1169',(#1430),#1424,.F.);
#1432=CARTESIAN_POINT('',(-2.71189704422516,0.266907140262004,1.11437509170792));
#1433=DIRECTION('',(0.,-1.,0.));
#1434=DIRECTION('',(1.,0.,0.));
#1435=AXIS2_PLACEMENT_3D('',#1432,#1433,#1434);
#1436=PLANE('',#1435);
#1437=ORIENTED_EDGE('',*,*,#418,.F.);
#1438=ORIENTED_EDGE('',*,*,#108,.T.);
#1439=ORIENTED_EDGE('',*,*,#932,.T.);
#1440=ORIENTED_EDGE('',*,*,#1408,.F.);
#1441=EDGE_LOOP('',(#1437,#1438,#1439,#1440));
#1442=FACE_BOUND('',#1441,.T.);
#1443=ADVANCED_FACE('F1180',(#1442),#1436,.F.);
#1444=CARTESIAN_POINT('',(0.,0.,1.4101567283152));
#1445=DIRECTION('',(0.,0.,-1.));
#1446=DIRECTION('',(-1.,0.,0.));
#1447=AXIS2_PLACEMENT_3D('',#1444,#1445,#1446);
#1448=CYLINDRICAL_SURFACE('',#1447,2.725);
#1449=ORIENTED_EDGE('',*,*,#403,.F.);
#1450=DIRECTION('',(0.,0.,-1.));
#1451=VECTOR('',#1450,1.);
#1452=CARTESIAN_POINT('',(-2.21511816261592,1.58709688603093,1.4101567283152));
#1453=LINE('',#1452,#1451);
#1454=EDGE_CURVE('E581',#393,#949,#1453,.T.);
#1455=ORIENTED_EDGE('',*,*,#1454,.T.);
#1456=ORIENTED_EDGE('',*,*,#950,.T.);
#1457=DIRECTION('',(0.,0.,-1.));
#1458=VECTOR('',#1457,1.);
#1459=CARTESIAN_POINT('',(-2.4820253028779,1.12480015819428,1.4101567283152));
#1460=LINE('',#1459,#1458);
#1461=EDGE_CURVE('E594',#402,#940,#1460,.T.);
#1462=ORIENTED_EDGE('',*,*,#1461,.F.);
#1463=EDGE_LOOP('',(#1449,#1455,#1456,#1462));
#1464=FACE_BOUND('',#1463,.T.);
#1465=ADVANCED_FACE('F1191',(#1464),#1448,.T.);
#1466=CARTESIAN_POINT('',(-2.4820253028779,1.12480015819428,1.4101567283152));
#1467=DIRECTION('',(0.50000000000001,0.866025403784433,0.));
#1468=DIRECTION('',(-0.866025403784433,0.50000000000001,0.));
#1469=AXIS2_PLACEMENT_3D('',#1466,#1467,#1468);
#1470=PLANE('',#1469);
#1471=ORIENTED_EDGE('',*,*,#409,.F.);
#1472=ORIENTED_EDGE('',*,*,#1461,.T.);
#1473=ORIENTED_EDGE('',*,*,#941,.T.);
#1474=ORIENTED_EDGE('',*,*,#96,.F.);
#1475=EDGE_LOOP('',(#1471,#1472,#1473,#1474));
#1476=FACE_BOUND('',#1475,.T.);
#1477=ADVANCED_FACE('F1202',(#1476),#1470,.F.);
#1478=CARTESIAN_POINT('',(-2.21511816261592,1.58709688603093,1.4101567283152));
#1479=DIRECTION('',(-0.50000000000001,-0.866025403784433,0.));
#1480=DIRECTION('',(0.866025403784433,-0.50000000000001,0.));
#1481=AXIS2_PLACEMENT_3D('',#1478,#1479,#1480);
#1482=PLANE('',#1481);
#1483=ORIENTED_EDGE('',*,*,#394,.F.);
#1484=ORIENTED_EDGE('',*,*,#49,.T.);
#1485=ORIENTED_EDGE('',*,*,#956,.T.);
#1486=ORIENTED_EDGE('',*,*,#1454,.F.);
#1487=EDGE_LOOP('',(#1483,#1484,#1485,#1486));
#1488=FACE_BOUND('',#1487,.T.);
#1489=ADVANCED_FACE('F1213',(#1488),#1482,.F.);
#1490=CARTESIAN_POINT('',(0.,0.,1.41015672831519));
#1491=DIRECTION('',(0.,0.,-1.));
#1492=DIRECTION('',(-1.,0.,0.));
#1493=AXIS2_PLACEMENT_3D('',#1490,#1491,#1492);
#1494=CYLINDRICAL_SURFACE('',#1493,2.725);
#1495=ORIENTED_EDGE('',*,*,#379,.F.);
#1496=DIRECTION('',(0.,0.,-1.));
#1497=VECTOR('',#1496,1.);
#1498=CARTESIAN_POINT('',(-1.12480015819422,2.48202530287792,1.41015672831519));
#1499=LINE('',#1498,#1497);
#1500=EDGE_CURVE('E352',#369,#685,#1499,.T.);
#1501=ORIENTED_EDGE('',*,*,#1500,.T.);
#1502=ORIENTED_EDGE('',*,*,#686,.T.);
#1503=DIRECTION('',(0.,0.,-1.));
#1504=VECTOR('',#1503,1.);
#1505=CARTESIAN_POINT('',(-1.58709688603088,2.21511816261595,1.41015672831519));
#1506=LINE('',#1505,#1504);
#1507=EDGE_CURVE('E578',#378,#676,#1506,.T.);
#1508=ORIENTED_EDGE('',*,*,#1507,.F.);
#1509=EDGE_LOOP('',(#1495,#1501,#1502,#1508));
#1510=FACE_BOUND('',#1509,.T.);
#1511=ADVANCED_FACE('F1224',(#1510),#1494,.T.);
#1512=CARTESIAN_POINT('',(-1.58709688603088,2.21511816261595,1.41015672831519));
#1513=DIRECTION('',(0.866025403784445,0.499999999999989,0.));
#1514=DIRECTION('',(-0.499999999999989,0.866025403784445,0.));
#1515=AXIS2_PLACEMENT_3D('',#1512,#1513,#1514);
#1516=PLANE('',#1515);
#1517=ORIENTED_EDGE('',*,*,#385,.F.);
#1518=ORIENTED_EDGE('',*,*,#1507,.T.);
#1519=ORIENTED_EDGE('',*,*,#677,.T.);
#1520=ORIENTED_EDGE('',*,*,#32,.F.);
#1521=EDGE_LOOP('',(#1517,#1518,#1519,#1520));
#1522=FACE_BOUND('',#1521,.T.);
#1523=ADVANCED_FACE('F1234',(#1522),#1516,.F.);
#1524=CARTESIAN_POINT('',(-1.12480015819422,2.48202530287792,1.41015672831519));
#1525=DIRECTION('',(-0.866025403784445,-0.499999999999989,0.));
#1526=DIRECTION('',(0.499999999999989,-0.866025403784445,0.));
#1527=AXIS2_PLACEMENT_3D('',#1524,#1525,#1526);
#1528=PLANE('',#1527);
#1529=ORIENTED_EDGE('',*,*,#370,.F.);
#1530=ORIENTED_EDGE('',*,*,#69,.T.);
#1531=ORIENTED_EDGE('',*,*,#692,.T.);
#1532=ORIENTED_EDGE('',*,*,#1500,.F.);
#1533=EDGE_LOOP('',(#1529,#1530,#1531,#1532));
#1534=FACE_BOUND('',#1533,.T.);
#1535=ADVANCED_FACE('F348',(#1534),#1528,.F.);
#1536=CLOSED_SHELL('',(#60,#87,#114,#141,#168,#195,#222,#249,#276,#303,#330,#357,#664,#971,#983,
#1005,#1017,#1029,#1051,#1063,#1075,#1097,#1109,#1121,#1143,#1155,#1167,#1189,#1201,#1213,#1235,
#1247,#1259,#1281,#1293,#1305,#1327,#1339,#1351,#1373,#1385,#1397,#1419,#1431,#1443,#1465,#1477,
#1489,#1511,#1523,#1535));
#1537=MANIFOLD_SOLID_BREP('B2',#1536);
#1538=ADVANCED_BREP_SHAPE_REPRESENTATION('',(#18,#1537),#14);
#1539=SHAPE_DEFINITION_REPRESENTATION(#9,#1538);
ENDSEC;
END-ISO-10303-21;
